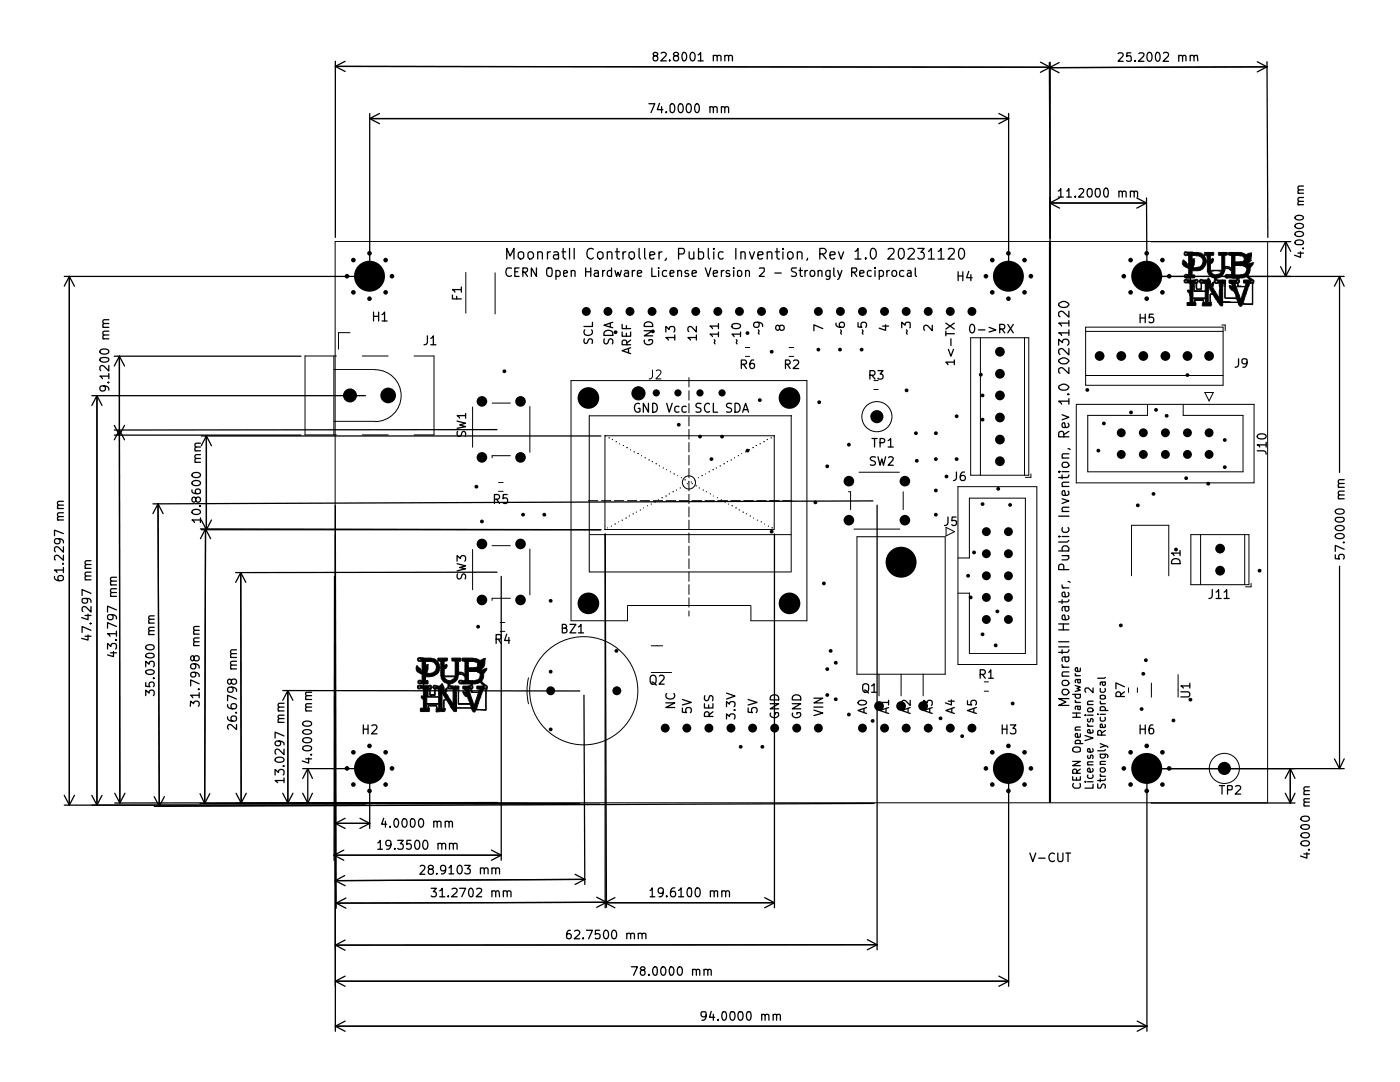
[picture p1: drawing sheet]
<svg xmlns="http://www.w3.org/2000/svg" width="279mm" height="216mm" viewBox="0 0 279 216" stroke-linecap="round" stroke-linejoin="round" font-family="sans-serif">
<g fill="none" stroke="#000" stroke-width=".2">
<path d="M66.9 48.2h186.1v112h-186.1zM93 54.4v8.1M98.8 54.4v8.3M236.1 51.9h.1M236.1 51.9l-.1 .3a.81 .81 0 0 0 .7 1.1M236.1 51.9a1.23 1.23 0 0 1 .9 1.4M236.2 52.2h.1M236.2 52.2l.3 .6 .6 .6M236.2 52.2l.5 .9M236.3 56.1h.1M236.3 50.6h.1M236.3 56.1h.2"/>
<path d="M236.3 55.1h.2M236.3 50.6h.2M236.5 56h.3l.1 .2-.3 .1zM236.5 50.5h.3l.1 .2-.3 .1zM236.6 50.4h.1M236.7 54.9h.1M236.7 53.3h.1M236.7 53.3l.5 .5v1.1l-.1-.1a.45 .45 0 0 0-.6 .1 .45 .45 0 0 0 0 .6h1v.4l-.9-.2-.3 .2 .1 .5 1 .1v1.5M236.7 54.9h.2v.4l-.4-.2M236.7 54.9l-.2 .2M236.9 56.1h1.6M237 58h.1"/>
<path d="M237 58l.1-.2 .3 .2M237 58l.4 .6M237.1 58h.1M237.1 53.4h.1M237.1 52.7h.1M237.1 52.7h.8M237.1 52.7v.7M237.1 58l.3 .3M237.1 51v1.7M237.4 58.6h.1M237.4 58.3h.1M237.4 58h.1"/>
<path d="M237.4 58.6l.1 1.8h-.6v.6h1.8l-.2-1.1h1.6l-.2 1.1h1.8l-.1-.6M237.5 59.9h.6M237.9 52.7h.1M237.9 51v.8l.4-.2M238.2 53.3h.1M238.2 53.3a1.39 1.39 0 0 0 1.8-1.6l-.7-.6h-2.7l-.3-.3 .2-.6 2.5 .2a1.83 1.83 0 0 1 1.8 1.7 1.83 1.83 0 0 1-1.6 1.9h-1.3v.9h.5v.6h-.8v.4l1.4-.1 .2 .3-.4 .5v1.1h.9v-1.1l-.3-.3 .1-.5 1.6 .1M238.2 56.5l-.1 2.9M238.2 52.2l-.3 .5M238.2 56.6v1.6h2.3v1.2h-3M238.2 52.2h.1M238.3 57.2h.1M238.3 51.6h.1"/>
<path d="M238.3 51.6l.1 .6-.2 1.1M238.4 56.5h.1M238.4 56.5l-.1 1.5M238.4 56.5l.3 .1 .1 1.1h1l.1-1.1h.6v1.5l-2.3-.1M238.6 56h.3v.3h-.3zM238.9 56.5h.1M239.4 56.1h.1M239.5 56.1l.1 .2M239.5 56.1l.2-.1h.2v.3h-.3M239.6 56.3h.1M240.3 58.1h.1M240.5 55.9h.1"/>
<path d="M240.5 57h1.4M240.8 51h.1M240.8 51h-.4v-.6h1.8v.5l-.5 .1-.1 .2v.7M240.8 51l.1 .1M240.9 51.1h.1M240.9 51.1l.1 3.2a2.66 2.66 0 0 0 1.4 1.2l-.1 .9 .2 .1M241 54.1h.1M241 52.2h.1M241 54.1h2.8M241 52.4h.7M241 52.2h.9M241.1 56h.1"/>
<path d="M241.1 55.8h.1M241.1 55.5h.1M241.1 55.5l.4 .4 .2 1 .1-.1M241.1 55.8v.2M241.1 55.5l-.2 .4M241.2 57.3h.1M241.2 57.3l-.1 3.1M241.2 57.4l.8 1.2M241.6 51.9h.1M241.6 54.1l.1 .1a.93 .93 0 0 0 .9 .7l.8-.3 .4-.5M241.7 52.4h.1M241.7 52.3h.1"/>
<path d="M241.7 52.3v.1M241.8 56.8h.1M241.8 52.3h.1M241.8 52.2h.1M241.8 51.7h.1M241.8 52.2v.1M241.8 52.3l-.1 .1M241.8 52.2l-.1 .1M241.9 52.2h.1M241.9 57h.1M242 51.6h.1M242 58.6h.1"/>
<path d="M242 56.7l-.1 .3M242 52l-.1 .2M242 51.6l-.4 .3M242 58.6l-.5 .1v1.7h-1.2M242.1 57.1h.1M242.1 51.8h.1M242.1 56.5h.1M242.1 51.8l-.1 .2M242.1 56.5l-.1 .2M242.2 56.3h.1M242.2 56.3h-.1l-.3 .5M242.2 56.3l-.2 1 1.3 2.2v-2.9l-.8-.1"/>
<path d="M242.3 56.2h.1M242.3 56.2h.2M242.4 55.6h.3M242.5 56.5h.1M242.6 56h.2l.2 .2-.3 .2-.2-.2zM242.7 55.6h.1M243.8 54.1h.1M243.8 55.9h.1M243.8 53.3h.7a1.08 1.08 0 0 1 1.3 .5h-.2a1.4 1.4 0 0 0-1.2-.5M244.2 56.6h.1M244.3 56.6h.1M244.3 56.6h-.2l-.1 .7v2.9"/>
<path d="M244.3 56.6l.1 2.9 2.4 .1 .3 .6M244.4 55.1h.1M244.4 53.3h.1M244.4 55.1l.5 .4h.8l1.2 .1-.2 .3h-1.4v.6l.2 .1M244.4 55.1h.3M244.6 54.9h.1M244.6 54.9l.3-.2 .9 .2M244.6 54.9l-.2 .2M244.7 55l.2-.1 .2 .3-.2 .1zM244.9 53.6h.1M244.9 53.3h.1M245.3 56.1h1.5"/>
<path d="M245.4 57h.1M245.4 57.1h.2M245.4 57v.1M245.5 56.6h.1M245.5 56.6h1.4M245.6 57.1h.1M245.6 57.1l.6 .8M245.6 57.1l.5 .7M245.7 51h.1M245.7 56.6l.3 .5-.6-.1M245.7 51l.1 .1M245.8 54.9h.1"/>
<path d="M245.8 52.3h.1M245.8 51.1h.1M245.8 54.9l-.1-.9-.5-.4h-.7a2.02 2.02 0 0 1-1.8 1.9v.2l.4 .2h1.5l-.1 3.5h2.2a1.88 1.88 0 0 0-1.1-1.7l-.2-.3v-.3M245.8 51.1v2.5a1.29 1.29 0 0 0-1.4-.4v-2.2l.5-.1v-.5h-1.7v.6l.6 .1v2.8h-2.2v-1.2a.66 .66 0 0 0 .5-.5 .66 .66 0 0 0-.1-.6M245.8 52.3h3M245.8 52.5h3M246.1 57.8h.1M246.5 51v1.3M246.5 52.9v2M246.5 56.6h.1M246.5 56.6l1.1 3.1M246.8 56h.3l.1 .1-.1 .2h-.3z"/>
<path d="M246.9 56.6h.1M246.9 56.6l.1 .6h1.5l-.9 2.5M247 56.8h.1M247.1 56.8v-.2a.45 .45 0 0 0 .1-.8v-.3h.2h.7l.6-.3 .8 .7h-1.3v.6l.5 .1-.2 .5h-1.4M247.1 56.8v.3M247.1 57.1h.1M247.1 52.9l1.1 .2M247.2 55.6h.1M247.2 56.1h.1M247.6 59.7h.1M248.2 56.1h1.4M248.2 53.1h.1"/>
<path d="M248.2 53.1l.5 .3a1.02 1.02 0 0 1-1 1.4l-1.9 .1M248.2 53.1h1.2M248.3 51.6h.1M248.3 51.6h.7M248.7 52.5h.1M248.7 52.5l.1 .1M248.8 52.6h.1M248.8 52.5h.1M248.8 52.3h.1M248.8 52.5v.1M249 51.6h.1M249.1 52.7h.1"/>
<path d="M249.4 53.1h.1M249.4 53h.1M249.4 50.8h.1M249.4 56.6h.1M249.4 56.6h.5v4h-1.5l-.3-.2M249.4 53v.1M249.4 50.8l-.4 .8M249.4 56.6l-1.3 3.8M249.5 53h.1M249.5 52.9h.1M249.6 52.9h.1M249.6 52h.1"/>
<path d="M249.6 52l-.7 .7h.9M249.7 52.9h.1M249.7 52.8h.1M249.7 52.8v.1M249.8 56h.1M249.8 52.8h.1M249.8 50.5h.1M249.8 50.5h-.6l-.5 .4-1.1-.5h-2.4v.5l.2 .1h1.7a1.19 1.19 0 0 1 1.2 .5v.3l-.3 .4-.8 .1M249.8 56l.3 .1-.1 .2-.4-.2M249.8 56l-.2 .1M249.8 52.8l-4 .1M249.8 50.5l-.2 1.5"/>
<path d="M249.8 52.7h.1M250.1 52.4h.1M250.1 56.5h.1M250.1 56.5l-.1 4.3-2-.1-.2 .3-.3 .1-.4-.7M250.1 52.4v.3a2.4 2.4 0 0 0-.8 1.8l-.2 .4 .7 .7a.49 .49 0 0 1 .4 .3 .49 .49 0 0 1-.1 .6M250.1 52.4l-.5 .1-.3 .2M66.6 71v15.8M66.6 73.7h8.2M67.1 71h-6.2v15.8h6.2M69.8 66.4h-2.2v3.3M72.3 71h5.2M74.9 73.8a5.2 5.2 0 0 1 5.2 5.1 5.2 5.2 0 0 1-5.2 5.2"/>
<path d="M82.6 71h4v15.8h-4M130.2 73.8v1.3a.57 .57 0 0 1-.7 .5M131 74l.6-.2 .2 .2 .1 .3-1 1.3h1M137.5 75.4v1.8M137.5 78v1.8M148.8 71.1h.8M148.8 69.3h.8M157.5 71.1h.9M157.5 69.3h.9M174.4 75.9h.9M174.4 77.7h.9M193.7 67.4h11.6v27.4h-11.6z"/>
<path d="M195.7 67.4v27.4M204.5 67.4v27.4M216.7 66.1h27.4M216.7 65.3h27.4v11.6h-27.4zM216.7 74.9h27.4M238.3 60.3h.1M238.3 60.1h.1M238.3 60.3l-.1 .1-.1-.2v-.6h2.4v.8M238.3 60.3v-.5h1.9l.1 .6M238.6 60.4h.1M240.1 60.2h.1M240.3 60.4h.1"/>
<path d="M240.5 60.4h.1M240.5 78.3h1.6l-.8 1.7zM241.6 60.4h.1M241.7 60.7h.1M243 60.2h.1M243 60.2l-.9-1.4h-.5v1.6M243 60.2l.7 .8h.3v-.6h3.1M243 60.2h4.1M243.8 64.9h.7v1.1M247.1 60.2h.1M247.1 60.4h1M248.1 60.4h.1"/>
<path d="M66.6 84.1h8.2M72.3 86.8h5.2M94.3 81.2v8M98.2 80.4h3.7M99.5 98h.9M99.5 96.3h.9M101.9 90.9h-3.7v.5M105.7 81.1v9.2M117.4 99.9h1.9M120.1 99.9h1.8M120.7 87h.1M120.7 87h33.8"/>
<path d="M120.7 87v18.7M121.5 87.4h.1M122.2 87.7h.1M122.6 99.9h1.9M122.9 88.1h.1M123.6 88.6h.1M124.4 88.9h.1M125.1 89.3h.1M125.2 99.9h1.9M125.8 89.7h.1M126.5 90.2h.1M127.3 90.5h.1"/>
<path d="M127.8 99.9h1.8M128 90.9h.1M128.7 91.4h.1M129.5 91.8h.1M130.1 92.1h.1M130.4 99.9h1.8M130.9 92.5h.1M131.4 99.7h.1M131.6 93h.1M132.1 99.3h.1M132.3 93.4h.1M132.8 99h.1"/>
<path d="M132.9 99.9h2M133 93.7h.1M133.5 98.5h.1M133.8 94.1h.1M134.3 98.1h.1M134.4 94.6h.1M135 97.8h.1M135.2 94.9h.1M135.5 99.9h1.9M135.7 97.4h.1M136 95.3h.1M136.4 96.9h.1"/>
<path d="M136.6 95.8h.1M137.2 96.5h.1M137.4 96.2h.1M137.5 80.5v1.9M137.5 83.1v1.9M137.5 85.7v1.9M137.5 88.3v1.9M137.5 90.8v2M137.5 93.5v1.8M137.5 96v2M137.5 98.6v1.9M137.9 96.2h.1"/>
<path d="M138.1 96.5h.1M138.1 99.9h1.9M138.6 95.8h.1M138.9 96.9h.1M139.4 95.3h.1M139.5 97.4h.1M140 94.9h.1M140.3 97.8h.1M140.7 99.9h1.9M140.8 94.6h.1M141 98.1h.1M141.5 94.1h.1"/>
<path d="M141.7 98.5h.1M142.2 93.7h.1M142.4 99h.1M142.9 93.4h.1M143.2 99.3h.1M143.3 99.9h1.9M143.7 93h.1M143.9 99.7h.1M144.4 92.5h.1M145.1 92.1h.1M145.9 91.8h.1M145.9 99.9h1.8"/>
<path d="M146.6 91.4h.1M147.3 90.9h.1M148 90.5h.1M148.4 99.9h2M148.8 90.2h.1M149.4 89.7h.1M150.2 89.3h.1M150.9 88.9h.1M151 99.9h1.9M151.6 88.6h.1M152.4 88.1h.1M153.1 87.7h.1"/>
<path d="M153.6 99.9h1.9M153.8 87.4h.1M154.5 87h.1M154.5 87v18.7M156.2 99.9h1.9M157.9 82.9v31.1M158 83h-40.4v31.1h40.3M169.3 98.1h.5v3.6M171.4 94.2h8.1M180.3 98.1v3.6M191.2 97.1h15.7v35.5h-15.7zM205.7 94.6v.6h-1.1"/>
<path d="M214.8 80.7h35.5v15.6h-35.5zM229 82.9h.1M229 80.7v2.2M236.1 80.7v2.2h12v11.2h-31v-11.2h11.9M94.3 109.6v8.1M98.2 108.9h3.7M101.9 119.4h-3.7v.4M105.7 109.6v9.1M117.8 106.7h40.1M120.6 105.7h33.8M121.2 105.3h.1M122 105h.1"/>
<path d="M122.7 104.6h.1M123.4 104.1h.1M124.1 103.8h.1M124.9 103.4h.1M125.6 103h.1M126.3 102.5h.1M127 102.2h.1M127.8 101.8h.1M128.4 101.3h.1M129.2 100.9h.1M130 100.6h.1M130.6 100.2h.1"/>
<path d="M137.5 101.2v1.9M137.5 103.8v1.9M137.5 106.3v2M137.5 109v1.8M137.5 111.5v2M137.5 114.1v1.9M137.5 116.7v1.9M137.5 119.3v1.9M144.6 100.2h.1M145.4 100.6h.1M146 100.9h.1M146.8 101.3h.1"/>
<path d="M147.5 101.8h.1M148.2 102.2h.1M148.9 102.5h.1M149.7 103h.1M150.4 103.4h.1M151.1 103.8h.1M151.9 104.1h.1M152.6 104.6h.1M153.3 105h.1M154 105.3h.1M170.4 105.6h9.2M171 107.1h17.6v27.4h-17.6z"/>
<path d="M188.8 105.2l1.7 .9-1.7 .8zM191.2 111.3h2.3v-11.9h11.1v31h-11.1v-12M191.2 118.4h2.3M193.5 118.4h.1M225.8 114.9v-10.1h7.5v10.1M237.7 106.7h11.6v10h-11.6zM239.6 106.7v10M248.4 106.7v10M249.7 116.4v.7h-1.1M83.1 132.8h.1M83.1 132.8v.2a1.22 1.22 0 0 0 1.1 1.5v1.3h-.7M83.1 132.8a1.4 1.4 0 0 1 1 1.5"/>
<path d="M83.2 133.3h.1M83.2 133.3l.7 .9M83.2 133.3l.3 .4M83.3 137.1h.1M83.3 137.1h.2M83.3 131.6h.2M83.4 133.5h.1M83.4 136.1h.2M83.5 135.8h.1M83.5 135.8v.6l1 .1v.3l-1-.1-.2 .2 .1 .5h.9l.2 .2-.1 1.3M83.5 137.1l.1-.2 .3 .2M83.5 131.6l.3-.2 .1 .3-.2 .1z"/>
<path d="M83.5 137.1l.2 .2 .2-.2M83.6 136l.3-.1 .1 .2-.3 .2zM83.6 133.8v.2l.5 .3M83.7 135.9h.1M83.7 131.2h.1M83.9 137.1h.1M83.9 137.1h1.7M84.1 134.3h.1M84.1 139l.2 .2M84.2 139h.1M84.2 139l.2 .4M84.2 133.6h.1"/>
<path d="M84.2 132v1.6M84.2 133.6v.8l-.2-.1M84.3 139.2h.1M84.3 139.2l.1 .2M84.4 139.5h.1M84.4 139.4h.1M84.4 138.9h.1M84.4 137.5h.1M84.4 139.5l.1 1.8h-.6v.7h1.8l-.1-.7M84.4 138.9h-.3v.4l.3 .2M84.9 133.6h.1M84.9 132v.8l.4-.2"/>
<path d="M85.2 137.5h.1M85.2 137.5l.1 1.6h2.2v1.3h-3M85.2 137.5v2.9M85.3 133.2h.1M85.3 138.9h.1M85.3 133.2l-.3 .4h-.8M85.3 133.2l-.4 .4M85.3 132.6h.1M85.3 132.6l.1 .9-.2 .8a1.29 1.29 0 0 0 1.6-.4 1.29 1.29 0 0 0-.1-1.7l-.7-.2-1.8-.1a.49 .49 0 0 1-.7 0 .49 .49 0 0 1-.1-.6h2.6a1.87 1.87 0 0 1 1.8 2 1.87 1.87 0 0 1-2 1.7h-.9v.8h.5v.7h-.8v.3l1.4-.1 .2 .5-.3 .3M85.4 137.5h.1M85.4 137.5v1.4M85.4 137.5h.3l.1 1.3h1.1v-1.2h.6v1.4l-2.1-.1"/>
<path d="M85.6 137l.2-.1 .1 .3-.2 .1zM85.9 137.5h.1M86.4 137.2l.3 .3v1.1h-.9l.1-1.1M86.4 137.2h.2M86.6 137.2h.1M87 137.2h.1M87 137.2l-.1-.3h-.2l-.1 .3M87 137.2l-.3 .1-.1-.1M87.3 139h.1M87.9 136.8h.1M87.9 132h.1M87.9 136.8l-.4 .1-.9-.2-.2 .5"/>
<path d="M87.9 136.8h.2M88 136.7h.1M88 136.7l-.1 .1M88 133.3h.7M88.1 135h2.7M88.1 135v.5a1.49 1.49 0 0 0 1.2 .9M88.1 136.5h.1M88.1 136.5l.4 .3 .2 1M88.1 136.7l.1 .2zM88.1 136.5l-.1 .2M88.2 136.7h.1M88.2 138.3h.1"/>
<path d="M88.2 138.3v3.1M88.2 138.3l.8 1.2M88.6 132.8h.1M88.6 132.8v-.7l.6-.2 .1-.6h-1.9v.5l.6 .3 .1 2.9M88.6 135a1.11 1.11 0 0 0 1.1 .8 1.11 1.11 0 0 0 1.1-.8M88.7 137.8h.1M88.7 133.3h.1M88.8 137.8h.1M88.8 133.3h.1M88.8 133.3h-.1M88.9 137.9l-1.4 .1M88.9 133.1l-.9 .1"/>
<path d="M89 139.5h.1M89 137.8l.2-.4-.3 .5M89 139.5l-.4 .1-.1 1.8h-1.1M89 137.8l-.1 .1M89.1 132.8h.1M89.1 132.8l-.2 .3M89.3 136.4h.1M89.3 137.2l.2 .3 .9 .1M89.3 137.2h.3M89.3 136.4v.8M89.4 136.6h.1M89.4 136.6h.3"/>
<path d="M89.6 137.1l.2-.1 .2 .2-.3 .1zM89.7 136.6a2.37 2.37 0 0 0 1.9 .3l-.1 3.5h2.3l-.4-1a.44 .44 0 0 0-.5-.5l-.5-.7M90.4 137.6h.1M90.4 137.6v2.9l-1.4-2.2 .2-.5v-.6l-.4 .4v.2M90.8 135h.1M90.8 136.9h.1M90.8 134.4h.7M91.1 137.6h.1M91.1 137.6v3.6M91.2 137.5h.1M91.2 137.5l.2 .1v2.9h2.4l.3 .7M91.2 137.5l-.1 .1"/>
<path d="M91.5 136.1h.1M91.5 134.4h.1M91.5 134.3h.8l.5 .4v.2a1.49 1.49 0 0 0-1.3-.5zM91.5 136.1h.2M91.6 135.8h.1M91.6 135.8l-.1 .3 .4 .4h1.9M91.9 134.5h.1M91.9 134.3h.1M91.9 135.9l.2 .1v.2h-.3l-.1-.1zM92.4 138.2h.1M92.4 138h.1M92.4 138.2h.3"/>
<path d="M92.4 138v.2M92.4 137.1h1.4M92.6 138.2h.1M92.6 138.2l.4 .3M92.7 138.2h.1M92.7 132h.1M92.7 137.5l.3 .7-.6-.2M92.7 138.2l.3 .3M92.7 132l2.1 .1a.61 .61 0 0 1 .5 .7 .61 .61 0 0 1-.7 .5l-1.1-.1v-1.2M92.8 135.8h.1M92.8 132h.1M92.8 132v2.5l-.4-.3-.9-.1v-2.1l.4-.1v-.6h-1.7l.1 .6 .5 .1v2.9h-2.2v-1.3l.3-.2a.58 .58 0 0 0 .3-.8l-.1-.1-.5 .3"/>
<path d="M92.8 135.8v-.7l-.3-.3-.4-.3h-.6a2.21 2.21 0 0 1-1.8 2.1M92.8 133.3h3.1M92.8 133.4h3M92.8 133.9h4M93 138.5l.2 .4M93 138.5l.2 .3M93.2 138.9h.1M93.2 138.8h.1M93.2 138.8v.1M93.6 137.5h.1M93.6 137.5l1.1 3.1M93.8 136.5h.1"/>
<path d="M93.8 136.5v.3l-1.4 .1v.6h1.5l.2 .7h1.4l-.8 2.4M93.8 137.1l.2-.2 .2 .2M93.8 137.1l.2 .2 .2-.2M94 137.8h.1M94.1 138h.1M94.2 136.6h.1M94.2 137.1h.1M94.2 136.6l.2 .7-.3 .2v.5M94.2 136.6l1.6-.5 .7 .8h-1.3v.6h.5l-.2 .6-1.4-.1M94.9 133.9l.3 .1M95.2 137.1h1.4M95.2 134a.93 .93 0 0 1 .6 1.1 .93 .93 0 0 1-1.1 .7h-3.1"/>
<path d="M95.2 134h1.3M95.3 132.6h.1M95.8 133.5h.1M95.8 133.4h.1M95.8 133.4v.1M95.8 133.3h.1M95.9 133.3h.1M96 132.6h.1M96 133.7h.1M96 133.7l.2 .1M96.1 132.4v.2h-.8M96.2 133.8h.1"/>
<path d="M96.2 133.8l1-.5-.7 1.1a2.09 2.09 0 0 1-.4 1.6l.7 .6 .3 .1 .2 .4M96.2 133.8h.7M96.3 132h.1M96.3 132l-.1 .2M96.4 134h.1M96.4 131.7h.1M96.4 137.6h.1M96.4 137.6l.5-.1v4.1l-1.8-.1M96.4 137.6l-1.3 3.9M96.4 131.7l-.4 .9M96.4 131.7l-.1 .3M96.5 134h.1"/>
<path d="M96.5 133.9h.1M96.5 133.9v.1M96.5 133.9l-.1 .1M96.6 133.9h.1M96.6 137.1l.3-.2 .2 .3-.2 .1zM96.6 133.9h-3.1v1.9M96.7 133.9h.1M96.8 133.9h.1M96.8 133.8h.1M96.8 131.4h.1M96.8 131.4l-1 .4-.8-.4-2.8-.1v.6l.5 .1M96.8 131.4l-.1 1.4-.7 .9"/>
<path d="M96.8 133.8v.1M96.9 133.8h.1M97.1 137.5h.1M97.3 137.1h.1M97.3 137.1l-.3 1.2v3.4l-2-.1-.3 .5M99.8 126h1M99.8 124.2h1M105.5 135.3l-.3 2.9 .3 2.2M125.2 120.8h24.7M125.2 121v2.9h-11.2v-48h47v48h-11.1v-2.9M130 134.2h4M130 128.9h2.2"/>
<path d="M137.5 121.9v1M175.4 134.5v4.4M179.8 134.5v4.4M184.2 134.5v4.4M196.4 136.1h.9M196.4 137.9h.9M225.2 137.2v1M227 137.2v1M229.8 136.3v2.8M235.1 134.6v4.5M84.5 140.9h.7M85.4 141.1h.1"/>
<path d="M85.4 141.1v-.3h1.8l.2 .6M85.4 141.1l-.1 .2h-.1v-.8h2.3v.9M85.6 141.3h.1M85.6 141.3l-.1-.4h1.6l-.1 1.2 1.7-.1 .1-.4M87.1 141.1h.1M87.4 141.4h.1M88.7 141.4h.1M88.8 141.6h.1M90.1 141.2l.5 .8h.5v-.7h3l.2 .6 .4 .2M93.9 141.2h.1M94.1 141.2h.1M94.1 141.2h-4.1l-.8-1.5h-.6v1.6l.2 .3"/>
<path d="M94.1 141.5h1M94.7 140.6h.1M94.7 142.1h.1M95.1 141.5h.1"/>
<circle cx="127.4" cy="78.5" r="1.31"/>
<circle cx="137.5" cy="96.3" r="1.31"/>
<circle cx="175" cy="83.1" r="3"/>
<circle cx="116.5" cy="137.8" r="10.8"/>
<circle cx="244.3" cy="153.3" r="3"/>
</g>
<g fill="none" stroke="#000" stroke-width=".25">
<path d="M66.9 12.2v35.2M66.9 13.2l2 1.1M68.9 12.2l-2 1M130.7 11.1l-.4-.4a.44 .44 0 0 1 .6-.3 .44 .44 0 0 1 .3 .6l-.7 .2-.2 .3 .1 .5 .3 .1h.4l.2-.3v-.3l-.4-.4M132 10.6l.2-.1h.4l.4 .2v.2l-.1 .2-1 1h1.1M133.6 12v.1M134.7 11.1a.34 .34 0 0 1-.3-.3 .34 .34 0 0 1 .3-.3h.4l.3 .3-.1 .2-.8 .3-.1 .5 .3 .3h.4l.3-.3-.1-.5-.2-.2M136.3 10.5h.1a.88 .88 0 0 1 .7 .8 .88 .88 0 0 1-.7 .8 1.35 1.35 0 0 1-.1-1.6zM137.9 10.6l.2-.1a.88 .88 0 0 1 .7 .8 .88 .88 0 0 1-.7 .8l-.2-.1-.2-.5zM139.3 11l.5-.5v1.6M139.3 12.1h1M142.4 11.1l.5-.1 .2 .2v.9"/>
<path d="M142.4 11v1.1M143.1 11.2l.3-.2 .5 .2v.9M144.7 11.2l.2-.2 .5 .2v.9M144.7 11v1.1M145.4 11.2l.3-.2 .4 .1 .1 1M207.6 12.4l2 1-142.7-.2M209.6 12.4v35.1l-.2-35M211.4 12.5l-3.8 1.9M223.1 10.7l.3-.2h.4l.4 .4-.1 .3-1 1h1.1M225.7 10.5h-.8l-.1 .8 .3-.2 .6 .1 .1 .9-.3 .1h-.4l-.3-.1M226.5 12.1v.1M227.3 10.7l.2-.2h.5l.2 .1 .1 .4-.1 .2-1 1h1.1"/>
<path d="M229.1 10.6l.2-.1a.96 .96 0 0 1 .4 1.6l-.2 .1a.96 .96 0 0 1-.4-1.6zM230.8 10.6l.1-.1a.96 .96 0 0 1 .4 1.6l-.2 .1a1 1 0 0 1-.3-1.6zM232.2 10.6l.3-.1h.4l.2 .1 .1 .4-.1 .2-1 1h1.1M235.2 11.2l.3-.2 .4 .1 .1 1.1M235.2 11v1.2M236 11.3a.35 .35 0 0 1 .3-.3 .35 .35 0 0 1 .4 .3v.8M237.5 11.2l.3-.2 .4 .1 .1 1M237.5 11v1.1M238.3 11.3l.2-.3 .5 .1 .1 1M250.9 12.3l2 1M252.9 12.3l.1 35.1M252.9 13.3l-43.5 .2 2 1"/>
<path d="M252.9 13.3l-2 1M73.8 22.6v31.7M73.8 23.7h127.5M73.8 23.7l1.9 1M75.7 22.6l-1.9 1.1M129.5 20.7h1.2l-.8 1.8M131.6 20.6l-.4 1.3h1.1M132 21.3v1.2M133 22.3v.2M133.9 20.8l.2-.1a.96 .96 0 0 1 .4 1.6l-.4 .2-.4-.4v-1.1zM135.6 20.8l.2-.1a.96 .96 0 0 1 .4 1.6l-.3 .2a.96 .96 0 0 1-.4-1.6zM137.2 20.8l.2-.1a.96 .96 0 0 1 .4 1.6l-.3 .2a.96 .96 0 0 1-.4-1.6z"/>
<path d="M138.8 20.9l.3-.2a1.01 1.01 0 0 1 0 1.8l-.3-.2-.2-.5zM141.7 21.5l.2-.2 .4 .1 .1 1.1M141.7 21.3v1.2M142.4 21.5l.2-.2 .4 .1 .1 1.1M144 21.5l.1-.1a.36 .36 0 0 1 .6 .1v1M144 21.3v1.2M144.7 21.5l.2-.2 .4 .1 .1 1.1M199.3 22.6l2 1.1M201.3 22.6v31.7M201.3 23.7l-2 1M209.5 39.5l.1 14.8M211.2 38.1l.5-.5v1.7"/>
<path d="M211.2 39.3h1M211.5 39.5l-2 1M212.9 38.1l.4-.5v1.7M212.9 39.3h.9M214.6 39.2v.1M215.3 37.8l.1-.1a.6 .6 0 0 1 .9 .2l-.1 .4-.9 1h1M217 37.9a.47 .47 0 0 1 .5-.3 .47 .47 0 0 1 .4 .3l.1 .7-.2 .6-.3 .1-.3-.1-.2-.2zM218.7 37.7l.6-.1a1.18 1.18 0 0 1-.1 1.7 .96 .96 0 0 1-.5-1.6zM220.4 37.7l.5-.2a1.29 1.29 0 0 1 0 1.8 .96 .96 0 0 1-.5-1.6zM223.3 38.3l.1-.1a.36 .36 0 0 1 .6 .2v.9M223.3 38.1v1.2M224 38.4l.2-.3 .5 .1v1.1"/>
<path d="M225.6 38.3l.2-.2 .5 .1 .1 1.1M225.6 38.1v1.2M226.4 38.4l.1-.3 .4 .1 .1 1.1M226.9 39.5l1.9 1M228.8 39.5l.1 14.8M259 38.6h1.1M260.1 39.4l-1 .1-.1 .4 .3 .3M260.1 37.9h-.8a.37 .37 0 0 0-.3 .3 .37 .37 0 0 0 .2 .4M260.1 37.1l-1 .1-.1 .4 .3 .3M12.8 55.2h60.1M13.8 55.2v105.5M13.8 55.2l1.1 1.9"/>
<path d="M13.8 55.2l-1 1.9M90.3 58.9v.7h1.8M91.1 59.1v.5M92.1 57.8h-1.8l.5 .5M92.1 57.3v1M101.1 51.7v-2.1l.7 1.5 .8-1.5v2.1M102.1 53.5h-.8a.88 .88 0 0 0-.4 1.1 .88 .88 0 0 0 1.1 .5l.1-.1M102.7 54.2h.6M103.5 50.4a.69 .69 0 0 1 .9 0l.1 .9-.2 .2a.54 .54 0 0 1-.5 .2 .54 .54 0 0 1-.4-.4zM103.6 53.5h-.9v1.7h.9M104.3 54.3h.6l.3-.2 .1-.4-.2-.2h-.8v1.7M104.7 54.3l.6 .9"/>
<path d="M105.5 50.4l.2-.2a.63 .63 0 0 1 .8 .5v.6l-.5 .4h-.3l-.3-.4zM107.1 53.5v1.7l-1.1-1.7v1.7M107.3 50.4l.1-.1a.54 .54 0 0 1 .8 .3v1.1M107.3 50.2v1.5M109.2 53.6l.1-.1h.7a1.37 1.37 0 0 1-.1 1.7 .6 .6 0 0 1-.8-.6zM109.3 50.2v1.5M109.9 50.2a.46 .46 0 0 0-.6 .5M110.5 50.3h.8l.2 .3v1.1M111 54.1l.5-.1 .3 .3v.5l-.2 .3h-.6M111 54v1.8M111.5 50.8h-.8a.47 .47 0 0 0-.3 .5 .47 .47 0 0 0 .3 .4h.5l.3-.2M112.1 50.2h.8"/>
<path d="M112.4 49.6v1.7l.5 .4M112.5 54.6l.7-.2v-.3l-.6-.1-.1 .2 .1 .9h.6M113.7 49.6v2.1M114 54.1l.3-.1 .4 .1 .1 1.1M114 54v1.2M114.6 49.6v2.1M116.9 54.2h1M116.9 53.5v1.7M117.9 53.5v1.7M118.4 49.7a.84 .84 0 0 0-1 .1 .84 .84 0 0 0-.3 1l.2 .5 .5 .4h.3l.3-.3M118.7 54.1h.6l.1 1.1M119.3 50.4a.61 .61 0 0 1 1.1 .3l-.1 .7a.55 .55 0 0 1-.6 .3 .55 .55 0 0 1-.4-.4z"/>
<path d="M119.4 54.4l-.6 .1a.35 .35 0 0 0-.2 .3 .35 .35 0 0 0 .2 .4l.6-.1M120.3 54v1.2M120.7 54l-.4 .3M121.2 50.4l.3-.2 .5 .1 .1 1.4M121.2 50.2v1.5M122 54.1l-.5-.1-.3 .3v.5l.2 .3h.6M122 53.5v1.7M122.7 54l.4 1.2 .2-.9 .4 .9 .3-1.2M122.8 50.2h.9M123.1 49.6v1.7l.3 .4h.3M124.3 50.2v1.5M124.7 54.1h.6l.1 1.1"/>
<path d="M124.9 50.2a.46 .46 0 0 0-.6 .5M125.4 54.4l-.6 .1a.35 .35 0 0 0-.2 .3 .35 .35 0 0 0 .2 .4l.6-.1M125.6 50.4l.3-.2 .5 .1a1.02 1.02 0 0 1 .1 1.1l-.2 .3h-.4l-.3-.3zM126.2 54v1.2M126.7 54l-.3 .1-.2 .2M127.2 54.6l.9-.2-.1-.3-.5-.1-.3 .2 .1 .9h.7M127.5 49.6v1.7l.3 .4M128.6 49.6v1.7l.3 .4M129.7 50.9l1-.1-.2-.5-.6-.1-.2 .4v.9l.2 .2h.4l.2-.2M130.1 53.5v1.7h.8M131.4 53.5h.1M131.4 54v1.2"/>
<path d="M131.5 50.2v1.5M132.1 50.2l-.5 .2-.1 .3M133 51.5l-.1 .4h-.2M133.1 54.1l-.6-.1-.3 .3v.5l.2 .3h.7M133.7 54.6l.8-.2-.1-.3-.5-.1-.2 .2 .1 .9h.6M135.3 54.1l.2-.1 .4 .1 .1 1.1M135.3 54v1.2M135.4 50.7h.9a.63 .63 0 0 0 .1-1l-1-.1v2.1M137.4 54.1l-.5-.1-.2 .2 .1 .3 .6 .2v.4h-.7M137.5 50.2l.1 1.3 .5 .2 .4-.3M138.1 54.6l.9-.2-.1-.3-.5-.1-.3 .2 .1 .9h.7M138.5 50.2v1.5"/>
<path d="M139.4 50.3h.8a1.02 1.02 0 0 1 .1 1.1l-.2 .3h-.4l-.3-.2M139.4 49.6v2.1M140.8 53.5l.5 1.7 .6-1.7M141.3 49.6v1.7l.3 .4M142.4 54.6l.8-.2-.1-.3-.5-.1-.2 .2v.9h.7M142.4 49.6v.1M142.4 50.2v1.5M144 54v1.2M144.3 50.3h-.7a1.02 1.02 0 0 0-.1 1.1l.2 .3h.4l.2-.2M144.5 54l-.4 .1-.1 .2M145.6 54.1l-.4-.1-.3 .2 .1 .3 .6 .2v.4h-.7M146.4 53.5h.1"/>
<path d="M146.4 54v1.2M146.9 49.6v2.1M147.2 54.1l.2-.1 .6 .1v.7l-.1 .3-.5 .1-.2-.2zM147.9 50.4l.2-.2 .5 .1 .1 1.4M147.9 50.2v1.5M148.8 54.1l.3-.1 .4 .1 .1 1.1M148.8 54v1.2M149.6 50.2l.5 1.5 .5-1.5M151.3 50.9l1-.1-.1-.5-.7-.1-.2 .4v.9l.2 .2h.4l.3-.2M151.6 53.5h.8l.1 .6-1 1.1h1M153.1 50.4l.4-.2 .5 .1v1.4M153.1 50.2v1.5"/>
<path d="M154.6 54.5h1.3M154.7 50.2h.9M155.1 49.6v1.7l.2 .4h.3M156.3 49.6v.1M156.3 50.2v1.5M157.4 50.3l.1-.1a.63 .63 0 0 1 .8 .5v.6l-.4 .4h-.4l-.2-.3a1.02 1.02 0 0 1 .1-1.1zM159 53.5h-1v.6l.8 .3 .2 .4-.4 .4-.7-.1M159.1 50.4l.1-.1a.54 .54 0 0 1 .9 .3v1.1M159.1 50.2v1.5M159.5 54h.6M159.7 53.5v1.4l.1 .2 .3 .1M160.7 54v1.2"/>
<path d="M161.2 54l-.4 .1-.1 .2M161.2 51.5l-.2 .4M161.8 54.1l.2-.1 .5 .1 .1 .7-.2 .3-.4 .1-.2-.2zM163.3 54.1l.2-.1 .5 .1v1.1M163.3 54v1.2M163.6 50.7l1-.1a.55 .55 0 0 0 .3-.6 .55 .55 0 0 0-.4-.4h-.9v2.1M164.1 50.7l.8 1M165.6 54v1.4l-.3 .4-.4-.1M165.6 54.1l-.5-.1-.3 .3v.5l.2 .3h.6M165.6 50.9l1.1-.1v-.2a.6 .6 0 0 0-1-.3v1.2l.3 .2 .6-.2M166.4 53.5v1.4l.3 .3M167.2 54l.4 1.2"/>
<path d="M167.3 50.2l.5 1.5 .6-1.5M168 54l-.6 1.6-.2 .2M170 54.3l.8-.1 .2-.2-.1-.5h-.9v1.7M170.4 54.3l.6 .9M170.6 50.2l.3-.1 .3-.5v2.1M170.6 51.7h1.2M171.6 54.6l.8-.2-.1-.3-.5-.1-.2 .2 .1 .9h.6M172.8 51.4v.3M173.9 54.1l-.5-.1-.3 .3v.5l.2 .3h.6M173.9 49.7l.2-.1a.68 .68 0 0 1 .8 .7 .98 .98 0 0 1-.8 1.4 1.7 1.7 0 0 1-.2-2zM174.6 53.5h.1M174.6 54v1.2"/>
<path d="M175.5 54.1l.5-.1 .3 .3v.5l-.2 .3h-.6M175.5 54v1.8M177 54v1.2M177.2 49.7a.87 .87 0 0 1 1.1 0v.7l-1.1 1.3h1.2M177.5 54l-.3 .1-.2 .2M178.1 54.1l.2-.1 .6 .1v.7l-.1 .3-.5 .1-.2-.2zM179.4 49.7l.6-.1a1.23 1.23 0 0 1 .4 1.7l-.6 .4a1.33 1.33 0 0 1-.4-2zM180.4 54.1l-.5-.1-.4 .3v.5l.2 .3h.7M181.1 54.1h.6l.1 1.1M181.2 49.7l.9-.1 .2 .1 .2 .5-1.4 1.5h1.4M181.8 54.4l-.5 .1a.35 .35 0 0 0-.3 .3 .35 .35 0 0 0 .3 .4l.5-.1M182.7 53.5v1.4l.2 .3"/>
<path d="M183.2 49.6h1.2l-.6 .7 .5 .1 .1 .4v.6l-.4 .3h-.6l-.2-.3M185.3 50.2l.6-.6v2.1M185.3 51.7h1.2M187.2 50.2l.3-.1 .3-.5v2.1M187.2 51.7h1.2M189.3 49.7h.1a.92 .92 0 0 1 1 0v.7l-1.2 1.3h1.3M191.2 54.2v1.8M191.2 55.1h.9M191.5 49.7l.2-.1a.68 .68 0 0 1 .8 .7 .98 .98 0 0 1-.8 1.4 1.7 1.7 0 0 1-.2-2zM192.1 54.2v1.8M193.3 54.1l-.4 1.3h1.1M193.8 54.8v1.2"/>
<path d="M209.5 40.5h19.3M209.5 40.5l2 1M228.8 40.5l-1.9 1M229.7 55.2h38.6M229.7 48.2h27.9M255.6 53.2l1 2M256.6 48.2v7M256.6 48.2l1 2M256.6 48.2l-1 2M257.6 53.2l-1 2M258.5 48.1a1.1 1.1 0 0 1 1.6 .2v.3l-.3 .2h-1l-.4-.3zM258.5 46.4a1.1 1.1 0 0 1 1.6 .2 .89 .89 0 0 1-.8 .6 .89 .89 0 0 1-.9-.6z"/>
<path d="M258.5 44.8a1.1 1.1 0 0 1 1.6 .2 .89 .89 0 0 1-.8 .6 .89 .89 0 0 1-.9-.6zM258.5 43.2a1.03 1.03 0 0 1 1.6 .3 .98 .98 0 0 1-1.7-.1zM259 50.5h1.1M259 40.8h1.1M259.5 50.2v1.1l-1.1-.4M260 49.6h.1M260.1 40.2l-1 .1-.1 .4 .2 .1M267.3 55.2v39.1M267.3 55.2l1 1.9M267.3 55.2l-1 1.9M18.3 78.9h54.6M19.3 78.9v81.8"/>
<path d="M19.3 78.9l1.1 2M19.3 78.9l-1 2M20 71.5l1-.2 .5 .1 .2 .3a.96 .96 0 0 1-1.6 .4l-.2-.3zM20 69.9a1.18 1.18 0 0 1 1.7 .2 .96 .96 0 0 1-1.6 .4l-.2-.3zM20.5 67.6h1.2M20.5 65.3h1.2M20.7 77l.3 .3v.4l-.3 .3h-.4l-.3-.2-.1-.5 .2-.2a1.18 1.18 0 0 1 1.6 .4v.3M21.5 76.3h.2M21.7 75.1h-1.8l.5 .5M21.7 72.9v1.1l-1-1-.3-.1-.3 .1-.2 .3v.4l.2 .3M21.7 66.8l-1.1 .1-.1 .5 .2 .2M21.7 66.1l-1.1 .1-.1 .4 .3 .2"/>
<path d="M21.7 64.6h-1.1l-.1 .5 .2 .2M21.7 63.8l-1.1 .1-.1 .4 .3 .3M21.7 74.5v1.1M22.8 71.1h37.3M23.8 71.1v15.7M23.8 71.1l1 1.9M23.8 71.1l-1 1.9M74.5 62.3v1.7M74.5 63.1h1.1M75.6 62.3v1.7M76.2 62.8l.5-.5v1.7M76.2 64h1.1"/>
<path d="M85.3 67v1.3a.57 .57 0 0 1-.7 .5M86 67.5l.5-.5v1.8M86 68.8h1M116.6 67.6a.67 .67 0 0 0 .2 .9l.4-.1 .2-.5a.47 .47 0 0 1 .4-.3 .47 .47 0 0 1 .4 .3v.6M116.7 65.8a.75 .75 0 0 0 .1 1 .75 .75 0 0 0 1 0 .62 .62 0 0 0 .3-1M118.2 64.3v.8h-1.7M120.6 67.6l-.1 .7 .2 .2h.5l.3-.7 .5-.2 .3 .3-.1 .7M120.6 66.2a.95 .95 0 0 1 1.1-.2 .95 .95 0 0 1 .6 .9h-1.8zM121.8 64.5v.7M122.3 64.3l-1.8 .6 1.8 .5M124.2 66.2v.9h1.7v-.9M124.2 64.7v.9h1.7"/>
<path d="M125 65v.6M125 66.5v.6M125.1 68.8l-.1-.8-.2-.1h-.5l-.1 .3v.6h1.7M125.4 69.6v.8M125.9 69.4l-1.7 .6 1.7 .6M125.9 67.9l-.8 .6M128.6 66h1.7l-1.7 1h1.7M128.6 67.9a.78 .78 0 0 0 .8 .9 .78 .78 0 0 0 .8-.9l-.7-.1v.2M128.6 64.6a.9 .9 0 0 1 1.1-.3 .9 .9 0 0 1 .6 .8h-1.7zM132.9 66.2v-1.1l.7 .6 .1-.5h.8l.2 .3v.5l-.2 .2M134.7 67.4h-1.8l.5 .5M134.7 66.8v1.1"/>
<path d="M139 67.4h-1.7l.5 .5M139 65.1v1.1l-1-1-.2-.1-.3 .1-.2 .3v.4l.2 .3M139 66.8v1.1M142.5 67.8l.2 .2-.2 .4 .2 .2M143.4 66.7h-1.7l.5 .5M143.4 65.1h-1.7l.5 .5M143.4 64.6v1M143.4 66.2v1M146.1 64.8a1.18 1.18 0 0 1 1.7 .2 .95 .95 0 0 1-.8 .6 .95 .95 0 0 1-.9-.5zM146.9 67.8l.2 .2-.2 .4 .2 .2M147.8 66.7h-1.7l.4 .5M147.8 66.2v1"/>
<path d="M148 72.7l.9-.1v-.6l-.3-.2h-.6v1.7M148.4 72.7l.6 .8M150.4 71.8h-.3l-.2 .2a1.23 1.23 0 0 0 0 1.5l.6-.1 .1-.6-.4-.3h-.3l-.3 .3M151.2 64.3l.3 .3-.1 .5-.2 .2h-.5l-.2-.2-.1-.5 .2-.2a1.18 1.18 0 0 1 1.6 .4v.3M151.3 65.8l.2 .3-.2 .3 .2 .3M155.6 65.2l.2-.3h.4l.3 .3-.2 .6-.5 .1-.4-.9-.3-.1-.2 .2-.1 .5 .2 .2 .2 .1 .4-.3M156.8 72.7l.8-.1v-.6l-.2-.2h-.6v1.7M157.1 72.7l.6 .8M158.4 72l.2-.2h.4l.3 .2 .1 .3-.1 .3-1 .9h1.1M164.2 65.6l-1.8-.8v1.2M166.8 64.5a.7 .7 0 0 0 .8 .8h.7a.6 .6 0 0 0 0-1h-.5l-.3 .3v.4l.3 .3M167.8 65.8l.1 .3-.1 .3 .1 .3"/>
<path d="M171.2 64.4v.8l.8 .1-.2-.2 .1-.6 .3-.2 .6 .1 .1 .2v.5l-.1 .2M172.1 65.8l.2 .3-.2 .3 .2 .3M173.6 74.9l.9-.1 .1-.3-.1-.4-.2-.1h-.7v1.6M174 74.9l.6 .7M175.2 74h1l-.6 .6 .5 .2v.7l-.2 .1h-.5l-.2-.1M176.1 65.1h1.2M176.7 64.8v1.1l-1.2-.4M180 65.4v-1.1l.6 .6 .2-.5h.8v1M180.9 65.8l.2 .3-.2 .3 .2 .3M186.1 64.9v1.1l-1-1-.2-.1-.4 .1-.1 .2v.5l.1 .2M188.8 66.1v.9M188.8 66.6h1.7"/>
<path d="M188.8 64.5l1.7 1.2M189.3 69.7l.5 1.4 .5-1.4M189.8 67.6v1.4M190.5 72.3h-1.7l.4 .5M190.5 71.8v1M190.5 64.5l-1.7 1.2M193.8 64.8l.1-.1a.89 .89 0 0 1 .6 .9 .89 .89 0 0 1-.6 .8 1.06 1.06 0 0 1-.1-1.6zM195.3 65.8h1.3M197.4 65.3l1.4 .5-1.4 .4M199.5 65.7l.9-.1 .1-.3-.1-.4-.2-.2h-.7v1.7M199.9 65.7l.6 .7M201.1 64.7l1.1 1.7"/>
<path d="M202.2 64.7l-1.1 1.7M211.3 68.9v-1.2l.7 .7a.49 .49 0 0 1 .5-.7h.4l.4 .4v.5l-.2 .3M211.4 77l.6-.3a1.02 1.02 0 0 1 1.3 .6 1.14 1.14 0 0 1-1.1 .6 1.14 1.14 0 0 1-.9-.7zM211.4 71.8l.6-.4a1.02 1.02 0 0 1 1.3 .7 1.09 1.09 0 0 1-1.1 .6 1.09 1.09 0 0 1-.9-.8zM211.4 60.5l.6-.3a1.02 1.02 0 0 1 1.3 .6 1.14 1.14 0 0 1-1.1 .6 1.14 1.14 0 0 1-.9-.7zM213.1 78.7h.2M213.3 73.4v1.1l-1.4-1.1-.5 .1-.1 .2v.5l.2 .3M213.3 69.6v1.2l-1.2-1.2h-.4l-.3 .1a.74 .74 0 0 0 .1 1M213.3 66.4h-2l.6 .5M213.3 64.5h-2l.6 .6M213.3 62.1v1.2l-1.4-1.2-.5 .2-.1 .1v.5l.2 .3M213.3 64v1.1"/>
<path d="M213.3 65.8v1.1M213.3 79.5v1.1M227.5 62.7v1.7M227.5 63.5h1.1M228.6 62.7v1.7M230.2 62.7h-.8l-.1 .8 .2-.2 .6 .1 .1 .2v.6l-.3 .2h-.4l-.2-.2M247.2 71.6v1.2a.57 .57 0 0 1-.7 .5M248.9 72.3l-.4 .3h-.3l-.3-.3v-.6h.9a1.18 1.18 0 0 1-.4 1.6h-.4M22.8 86.8h37.3M22.8 84.9l1 1.9M23.8 85.8l.1 74.4M23.8 85.8l1 2"/>
<path d="M23.8 85.8l-1 2M24.8 84.9l-1 1.9M38.3 97.7v.4a1.22 1.22 0 0 0 1.7 .2l-.1-.6-.6-.1-.3 .3 .1 .5 .2 .1M38.4 96.1a.96 .96 0 0 1 1.6 .4 .95 .95 0 0 1-.9 .4 .95 .95 0 0 1-.8-.6zM38.4 94.5a.96 .96 0 0 1 1.6 .4 .95 .95 0 0 1-.9 .4 .95 .95 0 0 1-.8-.6zM38.9 92.2h1.1M38.9 90h1.1M39.1 99.5l.3-.3 .4 .1 .2 .2-.1 .5-.5 .2-.2-.2-.3-.7-.3-.1-.2 .2-.1 .5 .2 .2 .2 .1 .4-.3M40 91.5l-1 .1-.1 .4 .2 .2M40 90.7l-1 .1-.1 .4 .3 .3M40 89.2l-1 .1-.1 .4 .2 .3M40 88.4l-1 .1-.1 .4 .3 .3"/>
<path d="M40.2 87h79.7M41.2 87v18.7M41.2 87l1 1.9M41.2 87l-1 1.9M91.2 84l1.7 .5-1.2 .3 1.2 .3-1.7 .4M91.3 86.1l-.1 .6 .2 .3h.5l.3-.8 .4-.1 .3 .3-.1 .7M92.9 82.9h-1.7l.5 .5M92.9 82.5v.9M98.7 99.6l.8-.1 .2-.2-.1-.5-.2-.1h-.7v1.8M99.1 99.6l.6 .9M99.2 85.7l-76.4 .1M101.2 98.7h-.7l-.1 .8 .2-.1h.4l.3 .3-.1 .6-.2 .2h-.4l-.2-.2"/>
<path d="M127.6 80.6a.87 .87 0 0 0-1 .6 .87 .87 0 0 0 .6 1.1l.5-.2v-.6h-.3M129.4 80.5v1.8l-1-1.8v1.8M130.3 80.5a.89 .89 0 0 1 .9 .9 .89 .89 0 0 1-.9 .9zM133.1 80.5l.5 1.8 .6-1.8M135.5 81.2l-.5-.1-.3 .3v.5l.1 .3h.7M136.9 81.2l-.5-.1-.3 .3v.5l.2 .3h.6M139.9 80.6l-.7-.1-.2 .1v.6l.7 .3 .2 .4-.3 .4-.7-.1M141.6 80.6a.68 .68 0 0 0-.8 .1 .68 .68 0 0 0-.2 .8 .62 .62 0 0 0 .3 .6 .62 .62 0 0 0 .7 0M142.4 80.5v1.8h.8M146 80.6l-.7-.1-.2 .1v.6l.7 .3 .2 .4-.3 .4-.7-.1M146.7 80.5a.9 .9 0 0 1 1 .9 .9 .9 0 0 1-1 .9zM148.2 82.3l.6-1.8 .6 1.8"/>
<path d="M148.4 81.7h.8M174 87.5h1M174.2 99.9l-143.7 .6M174.5 87.5v1.7M174.7 91.2a.74 .74 0 0 0-1 .2l.2 .4 .6 .3 .2 .2-.1 .4-.2 .1h-.7M175.2 91.1l.4 1.7 .4-1.2 .3 1.2 .4-1.7M175.6 88.3h.8l.2-.5-.4-.3h-.6v1.7M177.2 87.9l.6-.4v1.7M177.2 89.2h1.1M177.3 91.3l.1-.1a.6 .6 0 0 1 .9 .2l-.1 .4-1 1h1.1M190.9 94.2v1.2a.55 .55 0 0 1-.6 .5M192.5 94.2a.7 .7 0 0 0-.9 .8v.5l.2 .3 .5 .1 .4-.4v-.3l-.4-.3-.5 .1-.2 .2"/>
<path d="M211.3 94.1l.1 .2 .1-.2-.1-.1-.1 .1h.2M212 99.5l1.3 .4-1.3 .6M212 82.8l1.3 .5-1.3 .5M212 94.8v.7M212 97.1h1.3M212 94.1h1.3M212 91.4h1.3M212.1 92.3l.8-.1 .4 .5v.2l-.4 .4h-.6l-.3-.4zM212.3 87.2v-.7a.46 .46 0 0 0-.6-.4l-.3 .1-.1 1h2M213.1 98l.2 .2v.4l-.3 .2h-1v-.8l.5-.1 .1 .9M213.1 89.5l.5 .2M213.1 84.5l.2 .2v.3l-.2 .2h-1.1a.6 .6 0 0 1 .2-.8h.3l.1 .9"/>
<path d="M213.3 96.2h-1.1a.49 .49 0 0 0-.1 .9M213.3 94.8l-.3 .5h-1.7M213.3 90.5h-1.1a.52 .52 0 0 0-.1 .9M213.3 80.1h-2l.6 .5M213.3 86.1l-1 .6M250.9 90h1.3a.57 .57 0 0 1 .5 .6M251 86.8a1.18 1.18 0 0 1 1.7 .2 .96 .96 0 0 1-1.6 .4l-.2-.2zM252.7 88.8h-1.8l.5 .4M252.7 88.3v.9M267.1 99.5h1.2M267.1 97.2h1.2M268.3 98.8h-1.1l-.1 .5 .1 .2"/>
<path d="M268.3 98l-1.1 .1-.1 .4 .2 .3M268.3 96.5l-1.1 .1-.1 .4 .1 .2M268.3 95.7l-1.1 .1-.1 .4 .2 .3M10.9 115a.7 .7 0 0 0 .7 .9h.7l.3-.2 .1-.5-.2-.3-.6-.1-.3 .2v.5l.3 .4M11.5 103.8h1.2M11.5 101.5h1.2M11.6 107.5l.4 .3v.4l-.4 .3h-.4l-.2-.2-.1-.5 .1-.2a1.18 1.18 0 0 1 1.7 .4v.3M12.5 112.5h.2M12.7 113.7h-1.8l.5 .6M12.7 110.8v1l-1.3-1-.4 .1-.1 .2v.4l.1 .2M12.7 109.1v1.1l-1.1-1-.2-.1-.4 .1-.1 .2v.5l.1 .2M12.7 106.5l-1.8-.7v1.1"/>
<path d="M12.7 103.1l-1.1 .1-.1 .4 .1 .2M12.7 102.3l-1.1 .1-.1 .4 .2 .3M12.7 100.8h-1a.37 .37 0 0 0-.2 .3 .37 .37 0 0 0 .1 .4M12.7 100l-1.1 .1-.1 .4 .2 .3M12.7 113.2v1.1M17 115.7h1.2M17 113.4h1.2M17.1 119.4h.2l.2 .3-.1 .5-.3 .2-.5-.1-.2-.3 .2-.6h1.1a.63 .63 0 0 1 .5 .8M18.2 118.4l-1.8-.8v1.2M18.2 114.9l-1.1 .1-.1 .4 .1 .3M18.2 114.2l-1.1 .1-.1 .4 .2 .2M18.2 112.6l-1.1 .1-.1 .5 .1 .2"/>
<path d="M18.2 111.9l-1.1 .1-.1 .4 .2 .2M22.1 119h1.1M22.1 116.7h1.1M23.2 118.2l-1.1 .1v.4l.1 .3M23.2 117.5l-1.1 .1v.4l.2 .2M23.2 115.9l-1.1 .1v.5l.1 .2M23.2 115.2l-1.1 .1v.4l.2 .2M31.5 100.5l.3 60.4M31.5 100.5l1.1 2M31.5 100.5l-1 2M38.4 101.9a.96 .96 0 0 1 1.6 .3 .95 .95 0 0 1-.9 .5 .95 .95 0 0 1-.8-.6zM39.8 101h.2"/>
<path d="M40 103.8h-1.7l.5 .5M40 105.5l79.9 .2h-79.7M40 103.3v1M40.2 103.8l1 1.9M41 105.5l-.2 54.8M41 105.5l1 2M41 105.5l-1 2M42.2 103.8l-1 1.9M48 114.3l.1 45.9M48 114.3l1.1 1.9M48 114.3l-1 1.9M66.8 115l-.1 56.7"/>
<path d="M66.9 106.7l.2 74.5M66.9 100.9v104.9M91.2 112.5l1.7 .4-1.2 .3 1.2 .3-1.7 .4M91.2 112v-1.1l.7 .6 .2-.5h.7l.1 .2v.5l-.1 .3M91.3 114.5l-.1 .7 .4 .3 .4-.1 .3-.8h.5l.1 .2-.1 .7M99.2 114.2l-52.2 .1M100 115v56.7M154.6 106.6v74.5M175 100.8v88.7M189.2 103.2v1.1a.57 .57 0 0 1-.7 .6M190.8 103.2h-.8l-.1 .7h.9v.8l-.3 .2-.6-.2M211.3 107.1h.2"/>
<path d="M211.3 109.9h2M211.3 103h2M212 116.7v.4l.3 .2M212 119.7v.7M212 117.3h1.3M212 110.9h1.3M212 107.1h1.3M212 102.1h1.3M212 109.9a.72 .72 0 0 1 .3-1h.6l.4 .4-.2 .6M212 105.3v.6l.3 .3h.6l.4-.3v-.4l-.2-.2M212.3 113.7l-.1-1-.2-.1-.6 .1-.1 1h2M213.1 110.9l.2 .2v.3l-.3 .3h-1"/>
<path d="M213.1 118.2l.2 .2v.4l-.3 .3-1-.1v-.8h.5l.1 .9M213.1 116l.5 .2M213.3 119.7v.1l-.3 .3h-1.7M213.3 107.8l-.3 .4h-1.7M213.3 101.2l-1.3 .1v.4l.1 .4M233.9 111.8a.9 .9 0 0 1 1.1-.3 .9 .9 0 0 1 .5 1h-1.7zM235.5 110.4h-1.7l.5 .5M235.5 109.9v1M241.9 117.6v1.3a.57 .57 0 0 1-.6 .5M242.7 118.2l.5-.6v1.8M242.7 119.4h1M244.3 118.2l.5-.6v1.8"/>
<path d="M244.3 119.4h1M266.5 110.7v.8h.8l-.1-.2v-.5l.3-.2 .6 .1 .2 .3-.2 .5M266.6 106.7a1.18 1.18 0 0 1 1.7 .2 .96 .96 0 0 1-1.6 .4l-.2-.2zM266.6 105.1a1.18 1.18 0 0 1 1.7 .2 .96 .96 0 0 1-1.6 .4l-.2-.2zM266.6 103.4l.2-.2h1.1l.4 .4a.96 .96 0 0 1-1.6 .4l-.2-.2zM266.7 101.7a.96 .96 0 0 1 1.6 .4 1.11 1.11 0 0 1-1.8 0zM267.3 113v40.4M268.1 108.2h.2M268.3 109.6l-1.8-.8v1.2M17 127h1.2M17 122.8h1.2M17.6 126.7v1l-1.3-.3"/>
<path d="M17.6 122.6v1.1l-1.3-.5M18 124.4h.2M18.2 125.8l-1.8-.8v1.2M18.2 121v1.1l-1.1-1-.2-.1-.3 .1-.2 .3v.4l.2 .2M21.5 129.5v-1.1l.6 .6 .2-.5h.8l.1 .2v.5l-.1 .3M22.1 130.3h1.1M22.2 122.6l.4 .4v.3l-.4 .4h-.4l-.3-.2v-.5l.1-.3a1.18 1.18 0 0 1 1.6 .4v.4M22.6 130v1l-1.1-.3M23.1 127.7h.1M23.2 126.4h-1.7l.5 .6M23.2 125l-1.7-.8v1.1M23.2 121.7l-1.7-.8v1.2"/>
<path d="M23.2 125.9v1.1M29.1 138.8v-1.1l.7 .6 .1-.5 .6-.1 .3 .3v.6l-.2 .2M29.1 136.2v.7l.8 .1-.1-.2v-.5l.3-.2h.4a.59 .59 0 0 1 .1 .9M29.1 133.1v-1.1l.7 .5 .1-.5h.6l.3 .3v.5l-.2 .3M29.2 133.8a1.28 1.28 0 0 1 1.6 .2 .89 .89 0 0 1-.9 .6 .89 .89 0 0 1-.8-.6zM29.2 130.6a.96 .96 0 0 1 1.6 .3 1.16 1.16 0 0 1-1.7 0zM29.2 128.9a.96 .96 0 0 1 1.6 .3 .95 .95 0 0 1-.9 .5 .95 .95 0 0 1-.8-.6zM29.7 126.6h1.1M29.7 124.3h1.1M30.6 135.3h.2M30.8 125.9h-1l-.1 .5 .1 .2M30.8 125.2l-1 .1-.1 .4 .2 .2"/>
<path d="M30.8 123.6l-1 .1-.1 .4 .1 .2M30.8 122.9h-.9a.35 .35 0 0 0-.2 .3 .35 .35 0 0 0 .2 .4M38.6 128.8h1.1M38.6 126.5h1.1M38.7 134.2l.3 .1 .1 .5a.6 .6 0 0 1-1 0v-.3a1.06 1.06 0 0 1 1.6 .2v.3M38.7 132.5l.4 .3v.3l-.4 .4-.6-.2v-.5a1.06 1.06 0 0 1 1.6 .2v.3M38.7 131.2l.4-.3h.3l.3 .3v.5l-.6 .2-.4-.4-.1-.6h-.4l-.1 .3v.5l.4 .2 .2-.4M39.6 137.5h.1M39.7 138.7h-1.6l.4 .5M39.7 136.4l-1.6-.7v1.2M39.7 128.1h-1l-.1 .5 .2 .2M39.7 127.3l-1 .1-.1 .4 .3 .3"/>
<path d="M39.7 125.8l-1 .1-.1 .4 .2 .2M39.7 125l-1 .1-.1 .4 .3 .3M39.7 138.2v1M46 133.5h1.2M46 131.2h1.2M46.2 137.1l.3 .4-.1 .5-.2 .1h-.4l-.3-.1-.1-.5 .2-.3a1.18 1.18 0 0 1 1.6 .4v.4M46.2 135.8l.3-.3 .5 .1 .2 .2-.1 .6-.6 .1-.2-.1-.3-.8-.2-.1-.3 .2-.1 .5 .2 .2 .2 .1 .4-.3M47.2 139.5l-1.8-.8v1.1M47.2 132.7l-1.1 .1-.1 .4 .2 .3M47.2 132h-1.1l-.1 .5 .3 .2M47.2 130.4l-1.1 .1-.1 .4 .2 .3M47.2 129.7h-1.1l-.1 .5 .3 .2"/>
<path d="M56.4 137.8l59.3 .1M57.4 137.8v22.4M57.4 137.8l1.1 1.9M57.4 137.8l-1 1.9M61 139.6h1.2M62.2 138.8l-1.1 .1-.1 .4 .2 .3M62.2 138.1h-1.1l-.1 .5 .3 .2M66.8 139l.1 37.7M99 127.5h.9l.1-.3-.1-.4-.2-.2h-.7v1.8M99.4 127.5l.6 .9M101.1 126.5l-.4 1.3h1M101.6 127.2v1.2"/>
<path d="M112.2 125.3h.8l.1-.4-.2-.2-.7-.1v1.7h.6l.4-.4a.46 .46 0 0 0-.5-.6M113.7 124.6h1.2l-1.2 1.7h1.2M115.4 125.1l.5-.5v1.7M115.4 126.3h1.1M116.5 138.7l.2 37.8M129.8 135a.6 .6 0 0 1 .7-.3 .6 .6 0 0 1 .4 .6v.6a.59 .59 0 0 1-.6 .6 .59 .59 0 0 1-.6-.6zM130.1 136.1l.3 .1 .6 .5M131.6 134.9l.2-.2h.4l.3 .2v.4l-1 1.2h1M133.1 138.4a.71 .71 0 0 0-.1 .9 .71 .71 0 0 0 .9 .2 .67 .67 0 0 0 .7-.4 .67 .67 0 0 0-.1-.7M136.2 139.6l1.8 .6-1.8 .5M140.7 138.8l-.1 .7 .2 .2h.5l.3-.8 .3-.1 .4 .3-.1 .7M145 138.3l1.7 .6-1.7 .6"/>
<path d="M149.3 139.6l1.8 .6-1.8 .5M153.8 139a.9 .9 0 0 1 1.1-.3 .9 .9 0 0 1 .5 1h-1.7zM158.2 139a.9 .9 0 0 1 1.1-.3 .9 .9 0 0 1 .5 1h-1.7zM162.4 139.3h1.8l-1.8 .9h1.8M171.3 140a1.03 1.03 0 0 1 1.6 .2 .96 .96 0 0 1-1.7 0zM172.3 136.6l.6-.2a1.05 1.05 0 0 1 .4 1.5 .6 .6 0 0 1-.7 .2 .6 .6 0 0 1-.4-.6zM172.5 137.7l.3 .1 .6 .5M173.9 136.9l.6-.5v1.7M173.9 138.1h1.1M177.3 139.7v1M181.7 139.7v1.1l-1-1-.2-.1-.4 .1-.1 .3 .1 .6M189.3 139.9h1.2"/>
<path d="M189.9 139.7v1l-1.2-.5M193.1 139.8v.8l.8 .1-.1-.3v-.5l.3-.2 .6 .1 .2 .3-.2 .6M195.6 134.6l.9-.1 .1-.3v-.4l-.3-.2h-.7v1.7M196 134.6l.6 .7M197.3 134.2l.4-.6v1.7M197.3 135.3h.9M211.3 129.1h2M211.3 128.1h2M211.3 125.7h2M211.3 124.5h2M212 132.6v.4l.3 .1M212 134.9h1.3"/>
<path d="M212 133.1h1.3M212 129.7v.7M212 135.9l.3-.1h.6l.4 .4v.2l-.4 .4-.8-.1a.56 .56 0 0 1-.1-.8zM212.1 137.6l.8-.1 .4 .5v.2l-.4 .4h-.6l-.3-.4zM212.2 124.5v1.2M212.5 131.1l.1 .7a.36 .36 0 0 0 .5 .2l.2-.2v-.5l-.2-.2M212.5 121l.1 .7a.36 .36 0 0 0 .5 .2l.2-.2v-.4l-.2-.3M213.1 122.8l.2 .3v.3l-.2 .2h-1.1a.6 .6 0 0 1 .2-.9h.3l.1 1M213.3 139.4h-2l1.4 .7-1.4 .7h2M213.3 134.1h-1.1a.52 .52 0 0 0-.1 .8M213.3 131.1l-1.3 .1v.8M213.3 129.7l-.3 .5h-1.7"/>
<path d="M213.3 121h-1.1a.6 .6 0 0 0-.2 .9M214.1 138.6h1.5v.5l-.3 .2-.5-.1-.2-.2 .1-.4M214.6 139.7v.2l.3 .3M214.6 136.8l1 .3-.7 .3 .7 .3-1 .3M214.6 134.4v.2l.3 .2M214.6 134.8h1M215 135.6l.1 .6h.5v-.6l-.9 .1v.5M215.6 133.3v.6l-.2 .1-.7-.1v-.6l.3-.1 .1 .8M218.1 139.9l-1 .1-.1 .4 .2 .2M218.1 137.3v.9l-.9-.9-.6 .1-.1 .5 .2 .2M219.6 139.9v.3l.2 .2M219.6 138.8h.9v.6h-.9z"/>
<path d="M219.6 137.4v.6l.2 .1h.5l.2-.1v-.6M219.9 136.1l.3 .7 .4-.2-.1-.5M220.6 136.1l-1 .1v.5M220.6 135.2l-.3 .1h-1.2M223.6 139v-.6l-.1-.3-.4-.1-.3 .2-.1 .8h1.7M224.4 137l-1.7-.7v1.2M224.4 138l-.8 .6M235.7 138h1.4l.3 .4v.3l-.3 .4h-1.4M237.4 136.9h-1.7l.5 .4M237.4 136.4v.9M12.8 158.7l1 2M14.9 158.7l-1.1 2"/>
<path d="M18.3 158.7l1 2M20.4 158.7l-1.1 2M22.9 158.3l1 1.9M24.9 158.3l-1 1.9M30.8 159l1 1.9M32.8 159l-1 1.9M38 140.9l.1-1 .5 .5 .1-.3 .3-.2 .6 .1 .1 .2v.5l-.1 .2M39.9 158.4l.9 1.9M41.9 158.4l-1.1 1.9M45.4 143a.7 .7 0 0 0 .8 .9h.7l.2-.2 .1-.5-.2-.2-.6-.1-.2 .1-.1 .6 .3 .3M45.4 140.6a.7 .7 0 0 0 .8 .8h.7l.2-.1 .1-.5-.2-.3-.6-.1-.2 .2-.1 .5 .3 .3M47 142.2h.2"/>
<path d="M47.1 158.3l1 1.9M47.2 144.6v1l-1.3-1-.3 .1-.2 .2 .2 .6M49.1 158.3l-1 1.9M54.9 154.6v-1.1l.7 .6 .2-.5h.7l.2 .3v.5l-.2 .2M55 151.3a1.18 1.18 0 0 1 1.7 .2 .96 .96 0 0 1-1.6 .4l-.2-.2zM55.5 144.1h1.2M55.5 141.9h1.2M55.7 147.9l.3 .3-.1 .4-.2 .2h-.5l-.2-.2-.1-.4 .2-.2a1.44 1.44 0 0 1 1.6 .3v.3M56.4 158.3l1 1.9M56.5 152.9h.2M56.7 155.7h-1.8l.5 .5M56.7 149.5v1.1l-1-1-.3-.1-.3 .1-.2 .2v.4l.2 .3"/>
<path d="M56.7 146.9l-1.8-.8v1.2M56.7 143.4l-1.1 .1-.1 .4 .2 .2M56.7 142.7l-1.1 .1-.1 .3 .3 .3M56.7 141.1l-1.1 .1-.1 .4 .2 .3M56.7 140.3l-1.1 .1-.1 .4 .3 .3M56.7 155.2v1M58.5 158.3l-1.1 1.9M60.4 153.4h12.5M60.4 155.3l1-1.9 1 1.9M60.4 158.3l1 1.9M60.6 149a.96 .96 0 0 1 1.6 .4 1.11 1.11 0 0 1-1.8 0zM60.6 147.4a.96 .96 0 0 1 1.6 .4 1.11 1.11 0 0 1-1.8 0z"/>
<path d="M60.6 145.8a1 1 0 0 1 1.6 .3 1.05 1.05 0 0 1-1.8-.1zM60.6 144.1a.96 .96 0 0 1 1.6 .4 1.11 1.11 0 0 1-1.8 0zM61 141.9h1.2M61 151.4h1.2M61.4 153.7v6.5M61.6 151.3v1l-1.3-.5M62 150.6h.2M62.2 141.1l-1.1 .1-.1 .4 .2 .3M62.2 140.4h-.9a.35 .35 0 0 0-.3 .4 .35 .35 0 0 0 .3 .3M62.4 158.3l-1 1.9M72.5 145.5h.9M72.5 144.7v1.7"/>
<path d="M73.4 144.7v1.7M73.8 154.2v11.1M74.2 144.8l.3-.1h.4l.2 .1 .1 .4-.1 .2-1 1h1.1M132.9 140.2h1.8l-1.8 1h1.8M136.2 141.3v.8l.8 .1-.1-.3v-.6l.3-.1 .6 .1 .2 .2v.4l-.2 .3M140.6 140.4v.9h1.7v-.9M141.4 140.7v.6M141.5 143l-.1-.8-.2-.2-.4 .1-.2 .3v.6h1.7M142.3 142l-.8 .6M145 143.5v-1.1l.6 .6 .1-.4 .2-.2 .6 .1 .2 .3v.4l-.2 .3M145 141v-1l.6 .5v-.3l.3-.2 .6 .1 .2 .1v.6l-.2 .2M146.5 141.7h.2"/>
<path d="M149.3 141.3v.8l.9 .1-.2-.3 .1-.6 .2-.1 .6 .1 .2 .2v.4l-.2 .3M153.7 140.4h1.7l-1.7 1h1.7M153.8 142.3a.8 .8 0 0 0 .4 .9 .8 .8 0 0 0 .9-.2 .52 .52 0 0 0 .1-.8h-.5v.3M158.1 140.4h1.7l-1.7 1h1.7M158.2 142.3a.8 .8 0 0 0 .4 .9 .8 .8 0 0 0 1-.2 .52 .52 0 0 0 0-.8h-.6v.3M162.4 141.7l1.8 .6-1.8 .5M162.4 141.1h1.8M172.4 141.3v.9M172.9 141.2l-1.7 .6 1.7 .6M176.8 141.3v.9M177.3 141.2l-1.7 .6 1.7 .6M177.3 140.2h-1.7l.5 .5"/>
<path d="M181.2 141.3v.9M181.7 141.2l-1.7 .6 1.7 .6M184.4 140.8v-1.1l.6 .5 .3-.5 .6 .1 .2 .3v.4l-.2 .3M185.5 141.3v.9M186.1 141.2l-1.7 .6 1.7 .6M189.9 141.3v.9M190.5 141.2l-1.7 .6 1.7 .6M194.4 141.3v.9M194.9 141.2l-1.8 .6 1.8 .6M200 145.5h1M200 144.7v1.7M201 144.7v1.7"/>
<path d="M201.3 154.2v42.6M201.6 144.7h1.1l-.6 .6 .5 .2v.8l-.2 .1h-.5l-.3-.1M214.1 155v.7h1.5v-.7M214.1 151.9h1.5l-1.5 .9h1.5M214.1 149.4a1.03 1.03 0 0 1 1.5-.1v.6l-.2 .1a1.09 1.09 0 0 1-1.3-.3zM214.1 143.1h1.5M214.1 142.3h1.5M214.2 156.3v.1a.56 .56 0 0 0 .3 .9l.9-.1 .2-.2-.1-.7M214.6 148.4h1.5M214.6 145.7h1M214.6 140.2h1M214.7 148.4l-.1-.4 .3-.3 .7 .1v.6"/>
<path d="M214.8 142.3v.8M214.8 155.1v.6M214.9 154.3v-.6a.47 .47 0 0 0-.4-.3 .47 .47 0 0 0-.4 .3v.6h1.5M215 140.9l.1 .6h.5v-.6h-.9v.6M215.6 146.4v.6l-.2 .1-.7-.1v-.6l.3-.1 .1 .8M215.6 145.1l-.9 .1-.1 .3 .2 .2M215.6 153.5l-.7 .5M216.5 156h.2M216.5 146.8l1.6 .5-1.6 .5M216.5 142.7h.2M217 144.5v.2l.4 .2M217 141.5l.4-.2h.4l.3 .2v.3l-.1 .2h-.8z"/>
<path d="M217 156h1.1M217 152.6h1.1M217 144.9h1.1M217 142.7h1.1M217 140.6h1.1M217.1 154.6l-.1 .5 .4 .2 .6-.1 .1-.1v-.5M217.1 150.7a.33 .33 0 0 0 0 .5 .33 .33 0 0 0 .4 .1l.1-.6h.3l.2 .2v.4M217.1 143.5l-.1 .3 .3 .3 .2-.1 .1-.5h.5v.6M218.1 153.4v.4l-.2 .2h-.8v-.6l.4-.1 .1 .7M218.1 149.4v.5l-.2 .2-.8-.1v-.6h.4l.1 .7M218.1 145.7v.4l-.2 .2-.8-.1-.1-.4 .5-.2 .1 .7M218.1 156.5v.8h-1.6"/>
<path d="M218.1 152h-1l-.1 .4 .2 .2M219.1 156.4l.1 .9h.4l.3-.7 .3-.2 .4 .4-.1 .5M219.1 142.5h.1M219.6 154.5v.2l.2 .2M219.6 153.4l.2-.2h.5l.2 .2 .1 .3-.3 .3h-.5l-.2-.1zM219.6 148.4l1.3 .5 .2 .2M219.6 143.1v.6l.2 .2h.5l.2-.2v-.6M219.6 155.4v.6M219.6 154.9h1M219.6 152.5h1M219.6 142.5h1M219.6 140.4h1"/>
<path d="M219.8 146.7v-.8l-.2-.1h-.4l-.1 .9h1.5M220.5 150.5l.1 .4-.2 .3-.6 .1-.2-.2v-.6h1.2l.3 .3-.1 .4M220.5 144.6v.6h-.9v-.6l.3-.1 .2 .7M220.5 141.8l.1-.5-.2-.2-.6-.1-.2 .2v.6h1.5M220.6 155.4v.2l-.3 .1h-1.2M220.6 151.9l-1 .1 .1 .5M220.6 149.6l-.3 .2h-1.2M220.6 148.8l-1 .3M220.6 145.8l-.8 .5M227.5 144.7v1.7M227.5 145.5h1.1M228.6 144.7v1.7"/>
<path d="M228.9 154.2v51.6M229.7 153.4h38.6M230.1 144.7h-.4a1.32 1.32 0 0 0-.3 1.6l.2 .1 .5-.1 .1-.2v-.4l-.3-.4-.5 .1-.1 .3M243.4 156.8h1M243.9 156.8v1.7M245 157.6l.8-.1 .1-.6-.2-.1h-.7v1.7M246.6 156.9l.2-.1h.5l.2 .1 .1 .4-1.1 1.2h1.1M256.5 158.3l1 1.9M257.5 153.4v6.8M257.5 153.4l.9 1.9M257.5 153.4l-1 1.9M258.4 158.3l-.9 1.9"/>
<path d="M260.2 158.5h1.1M261.3 159.4h-1l-.1 .4 .3 .3M261.3 157.8l-1 .1-.1 .4 .2 .2M261.3 157l-1 .1-.1 .4 .3 .3M266.3 151.4l1 2M268.3 151.4l-1 2M12.8 160.7h60.1M39.9 160.3l79.9 .2M56.4 160.2l59.3 .1M66.7 170.6h33.3M66.7 170.6l1.9 1.1M66.9 164.3h6.9"/>
<path d="M66.9 164.3l2 1M66.9 175.7l2 1M68.6 169.6l-1.9 1M68.8 174.7l-1.9 1M68.9 163.3l-2 1M69 179.2l-1.9 1M71.8 163.3l2 1M73.8 164.3l-2 1M75.4 168.2l.5-.5v1.8M75.4 169.5h.9M76.6 163.3l-.4 1.2h1M76.9 163.9v1.2"/>
<path d="M77.8 164.9v.2M78 168.4l-.3 .4-.5-.1-.2-.3v-.4l.2-.2 .5-.1 .2 .1a1.18 1.18 0 0 1-.4 1.7h-.3M78.8 163.5l.2-.1a.93 .93 0 0 1 .6 .8 .93 .93 0 0 1-.6 .9l-.2-.2-.2-.5zM78.8 169.3v.2M79.4 167.7h1.1l-.6 .7 .5 .1v.8l-.3 .2h-.5l-.2-.2M80.4 163.5l.2-.1a.88 .88 0 0 1 .7 .8 .88 .88 0 0 1-.7 .9l-.2-.2-.2-.5zM82 163.5l.3-.1a.88 .88 0 0 1 .6 .8 .88 .88 0 0 1-.6 .9l-.4-.4zM82 167.7h-.8v.8l.2-.1h.5l.2 .3-.1 .6-.3 .2-.5-.2M82.9 167.8l.3-.1a.96 .96 0 0 1 .4 1.6l-.2 .2a.96 .96 0 0 1-.5-1.7zM83.7 163.5l.2-.1a.88 .88 0 0 1 .7 .8 .88 .88 0 0 1-.7 .9l-.2-.2-.2-.5zM83.9 172.8l.6-.1 .2 .1 .1 .4-1 1.3h1M84.5 167.8l.3-.1a.96 .96 0 0 1 .4 1.6l-.2 .2a.96 .96 0 0 1-.5-1.7z"/>
<path d="M85.8 173.4l-.3-.3 .1-.3 .2-.1 .5 .1 .2 .2-.1 .3-.8 .2-.1 .3v.3l.3 .4h.3l.4-.4-.1-.5-.3-.2M86.1 177.2h1l-.6 .7 .5 .2v.7l-.3 .1h-.4l-.2-.1M86.6 164l.2-.1 .4 .1v1.1M86.6 163.9v1.2M87.2 174.3v.1M87.2 164.1l.3-.2 .4 .1 .1 1.1M87.4 168.4l.3-.1 .4 .1 .1 1.1M87.4 168.3v1.2M87.8 177.8l.5-.6v1.7M87.8 178.9h1M88.2 168.5l.2-.2 .5 .1v1.1M88.9 164l.2-.1 .4 .1 .1 1.1"/>
<path d="M88.9 163.9v1.2M88.9 173.4l-.3 .4h-.3l-.4-.4v-.4l.2-.2 .5-.1 .3 .1a1.17 1.17 0 0 1-.5 1.6h-.3M89.4 178.8v.1M89.6 164.1a.35 .35 0 0 1 .4-.2 .35 .35 0 0 1 .3 .2v1M89.6 173.2l.4-.5v1.7M89.6 174.4h.9M89.7 168.4l.3-.1 .4 .1 .1 1.1M89.7 168.3v1.2M90.2 177.4l.3-.2h.4l.2 .2 .1 .4-.1 .2-1 .9h1.1M90.5 168.5l.2-.2 .4 .1 .1 1.1M91.5 172.8l.1-.1a.89 .89 0 0 1 .7 .8 .89 .89 0 0 1-.7 .9 1.06 1.06 0 0 1-.1-1.6zM91.7 177.2h1.2l-.7 1.7"/>
<path d="M92.8 172.7h1.1l-.6 .7h.5v.8l-.3 .2h-.5l-.2-.2M93.7 177.4l.2-.2a1.01 1.01 0 0 1 .2 1.7 .91 .91 0 0 1-.4-1.5zM95.1 177.4l.3-.2h.4l.3 .5v.2l-1.1 1h1.1M95.9 173.4l.2-.2 .5 .1v1.1M95.9 173.2v1.2M96.6 173.4l.3-.2 .4 .1 .1 1.1M98.1 169.6l1.9 1M98.2 177.9l.2-.1h.4l.1 1.1M98.2 173.4l.2-.2 .4 .1 .1 1.1M98.2 173.2v1.2M98.2 177.8v1.1M98.9 178l.3-.2h.3l.2 1.1"/>
<path d="M98.9 173.4l.3-.2 .4 .1 .1 1.1M99.3 160.1l-76.4 .1M100 170.6l-1.9 1.1M100.5 177.9l.2-.1h.4l.1 1.1M100.5 177.8v1.1M101.2 178l.3-.2h.4l.1 1.1M114.8 174.5l1.9 1M116.7 175.5l-49.8 .2M116.7 175.5l-1.9 1M119.1 179l1.9 1-1.9 1.1M122.7 179.1l-1.9 1 1.9 1M129.7 177.7l.5-.5v1.7"/>
<path d="M129.7 178.9h1M132.4 177.9l-.4 .4h-.3l-.3-.4v-.4l.1-.3h.5l.3 .1a1.18 1.18 0 0 1-.4 1.6h-.4M133.1 178.8v.1M134.7 177.2a.7 .7 0 0 0-.9 .7v.7l.2 .3h.5l.2-.1 .1-.6-.1-.3-.5-.1-.4 .4M135.4 177.7l.5-.5v1.7M135.4 178.9h1M137.4 177.2h.3l.3 .1v1v.5l-.3 .1a.96 .96 0 0 1-.4-1.6zM138.9 177.3l.2-.1a.96 .96 0 0 1 .5 1.6l-.3 .1a.96 .96 0 0 1-.4-1.6zM141.8 177.9l.2-.1h.4l.1 1.1M141.8 177.8v1.1M142.5 178l.3-.2h.4v1.1M144.1 177.9l.2-.1h.4l.1 1.1"/>
<path d="M144.1 177.8v1.1M144.8 178l.3-.2h.4l.1 1.1M152.6 179.1l2 1M174.5 160.3l-143.7 .6M205.5 170.2l.6 1.7 .6-1.7M207.3 171.2h1.3M210.4 170.4a.8 .8 0 0 0-1.1 .5 .8 .8 0 0 0 .8 1l.3-.2M211.1 170.2v1.4l.4 .3h.3l.3-.3v-1.4M212.7 170.2h1M213.1 170.2v1.7M229.7 160.2h28.7M259.7 168a.96 .96 0 0 1 1.6 .4 .95 .95 0 0 1-.9 .4 .95 .95 0 0 1-.8-.6z"/>
<path d="M259.7 166.4a.96 .96 0 0 1 1.6 .3 .95 .95 0 0 1-.9 .5 .95 .95 0 0 1-.8-.6zM259.7 164.7a1.28 1.28 0 0 1 1.6 .2 .89 .89 0 0 1-.8 .6 .89 .89 0 0 1-.9-.6zM259.7 163.1a.96 .96 0 0 1 1.6 .3 .95 .95 0 0 1-.9 .5 .95 .95 0 0 1-.8-.6zM260.2 170.4h1.1M260.2 160.8h1.1M260.8 170.1v1.1l-1.3-.4M261.2 169.5h.1M261.3 160.1h-1l-.1 .5 .2 .2M66.9 188.6l2 1M66.9 195.8h134.4M66.9 195.8l2 1M67.1 180.2l1.9 1"/>
<path d="M68.9 187.6l-2 1M68.9 194.8l-2 1M113.8 185.6a.72 .72 0 0 0-.7 .8v.6l.3 .3 .5-.1 .1-.6a.54 .54 0 0 0-.9 0M114.7 185.8l.2-.2h.5l.2 .2 .1 .3-.1 .3-1 .9h1.1M116.4 187.2v.1M117 185.6h1.2l-.7 1.7M119.7 185.6h-.9v.9l.2-.2h.4l.4 .3v.4l-.2 .2-.6 .1-.2-.1M120.6 185.8l.3-.2a.89 .89 0 0 1 .6 .9 .89 .89 0 0 1-.6 .8l-.3-.1-.2-.6zM121 181.1l-.2-74.5v74.5M122.2 185.8l.3-.2a.89 .89 0 0 1 .6 .9 .89 .89 0 0 1-.6 .8l-.3-.1-.2-.6zM125.1 186.4l.2-.2 .6 .2v.9M125.1 186.2v1.1"/>
<path d="M125.9 186.4l.2-.2 .5 .2v.9M126 192.9h1.2l-.8 1.7M127.4 186.3l.5-.1 .2 .2v.9M127.4 186.2v1.1M128.1 186.4l.3-.2 .5 .2v.9M128.1 193.6l-.3-.3a.47 .47 0 0 1 .5-.4 .47 .47 0 0 1 .4 .4l-.7 .4-.2 .2 .1 .5 .2 .2 .5-.1 .1-.2v-.4l-.3-.3M129.5 194.4v.2M130.4 193.1l.5-.2a1.16 1.16 0 0 1 0 1.7 .91 .91 0 0 1-.5-1.5zM132 193.1l.3-.2a.88 .88 0 0 1 .6 .9 .88 .88 0 0 1-.6 .8l-.3-.2-.1-.5zM133.7 193l.2-.1a.88 .88 0 0 1 .6 .9 .88 .88 0 0 1-.6 .8 1.35 1.35 0 0 1-.2-1.6zM135.3 193.1l.3-.2a.88 .88 0 0 1 .6 .9 .88 .88 0 0 1-.6 .8l-.3-.2-.1-.5zM138.2 193.6l.3-.2 .4 .1 .1 1.1"/>
<path d="M138.2 193.4v1.2M139 193.7l.1-.3 .5 .1 .1 1.1M140.5 193.6l.3-.2 .4 .1 .1 1.1M140.5 193.4v1.2M141.3 193.7a.35 .35 0 0 1 .3-.3 .35 .35 0 0 1 .3 .3v.9M154.6 180.1l-87.5 .1M154.6 180.1l-2 1M173.1 187.5l1.9 1M175 188.5l-108.1 .1M175 188.5l-1.9 1M199.3 194.8l2 1M201.3 195.8l-2 1"/>
<path d="M66.9 204.8h162M66.9 204.8l2 1M68.9 203.7l-2 1.1M140.9 202.6l-.3 .3h-.4l-.3-.3v-.5l.2-.2 .7 .1a1.18 1.18 0 0 1-.4 1.6h-.3M141.9 201.8l-.3 1.2h1M142.4 202.4v1.2M143.3 203.4v.2M144.2 202l.5-.1a1.18 1.18 0 0 1-.1 1.7h-.2a1.35 1.35 0 0 1-.2-1.6zM145.8 202l.6-.1a1.18 1.18 0 0 1-.1 1.7 .96 .96 0 0 1-.5-1.6zM147.4 202l.6-.1a1.18 1.18 0 0 1-.1 1.7 .96 .96 0 0 1-.5-1.6zM149.1 202l.5-.1a1.1 1.1 0 0 1-.2 1.7l-.3-.2-.1-.5zM152 202.6l.1-.1a.36 .36 0 0 1 .6 .1v1"/>
<path d="M152 202.4v1.2M152.7 202.6l.2-.2 .5 .1 .1 1.1M154.3 202.6l.3-.2 .4 .1v1.1M154.3 202.4v1.2M155 202.6l.2-.2 .5 .1v1.1M226.9 203.7l2 1.1M228.9 204.8l-2 1"/>
</g>
<g fill="#000">
<path d="M236.5 50.2l2.9 .3a1.8 1.8 0 0 1 1.4 1.8 1.8 1.8 0 0 1-1.6 1.7h-1.3v.9h.5v.6h-.8v.4l1.4-.1 .2 .3-.4 .5v1.1h.9v-1.1l-.3-.5 .5 .2v-.3h-.2l-.3 .1 .1-.3 .2-.1 1.4 .3v-.2l-.2 .1 .2-.4 .5 .5 .1 .9 .4-.6h.1l-.2 1 1.3 2.2v-2.9h-.6l-.4-.2v-.2l.4 .2 .3-.2-.2-.2-.5 .2 .1-.6h.3l.4 .3h1.5l-.1 3.5h2.2v-.1a2.27 2.27 0 0 0-1.1-1.6l-.2-.3v-.3h.2l.6 .8-.6-.8h-.3h.7l-.2-.5h-.2h.9l1 2.9 .1 .2 .9-2.5h-1.5v-.4l.1 .3h1.4l.2-.5-.5-.1v-.4h1.4l.2 .2h.2l.1-.2-.2-.1-.3 .1h-1.4v-.2h1.3l-.8-.7-.6 .3h-.7h-.2v.3a.72 .72 0 0 1-.2 1l-.1-.2-1.6-.1v-.4h1.5v.2h.3v-.3l-.3 .1h-1.5v-.2h1.4l.2-.3-.1-.1h-1.9l-.5-.4 .5 .2 .2-.1-.2-.3-.5 .2 .5-.4 .9 .2 2.3-.1a1.07 1.07 0 0 0 .6-1.4l-.5-.3 1.3-.1-1.3 .1-1.7-.2 3.1 .1-3.1-.1v2h-.7l-.1-.9-.5-.4h-.7a2.02 2.02 0 0 1-1.8 1.9l-.3 .1-.2-.1a1.98 1.98 0 0 1-1.2-1.4l.7 .1a.93 .93 0 0 0 .9 .7l.8-.3 .4-.5h-2.8v-1.7l.8-.1-.8 .1v-.2h.9l.2-.4-.2 .4h-.9l-.1-1.1-.5-.1v-.6h1.8v.5l-.5 .1-.1 .2v.7l.4-.3 .1 .2-.2 .7-.3 .2v1.2h2.2v-.6l1.2 .1 .8 .4-.8-.5h-1.2v-2.2l-.6-.2v-.5h1.7v.5l-.5 .1v2.2h.8l.6 .4v-.7l4-.1-4 .1v-.4l3 .1-3-.1v-.2h3.1h-3.1l-.1-1.3h.8v1.3l1.5-.1 .2-.2 .1-.4h.8l.3-.8-.4 .8a1.19 1.19 0 0 1-1.2-.5l-2.4-.1-.2-.1v-.5h2.4l1.1 .5 .5-.4h.6a2.06 2.06 0 0 1-.9 2.2l.9 .1 .1-.1h-.8l.9-.3 .1 .3a2.4 2.4 0 0 0-.8 1.8l-.2 .4 .7 .8a.5 .5 0 0 1 .5 .4 .5 .5 0 0 1-.3 .5v4.2l-2-.1-.2 .3-.3 .1-.4-.5v-.2l2.8 .2v-4h-.6l-1.2 3.8h-4.1v.6h-.5l-.5-.8h4.1l-.3-.6-2.4-.1-.1-2.9h-.2l-.1 .7v2.9h-1l-.9-1.4h-.5l.1 2.2h-1.8l.2-1.1h-1.6l.2 1.1h-1.8v-.6h.6v-.5h.6l.1 .5 .1-.6h1.9l.1 .6h1.2v-1.7l.5-.1-.8-1.3-.1 3.1h-.7l.1-.1v-.7h-2.4v.3h-.6v-.5h3v-1.2h-2.3v-.2l2.3 .1v-1.1h1.4l.2-.5-.2 .5h-1.4v-.4h-.6l-.1 1.1h-1l-.1-1.1-.3-.1-.1 1.5-.1-1.5-.1 2.9h-.6v-.2a1.15 1.15 0 0 0-.5-1.1l.1-.1 .3 .3-.3-.3h-.1l.1-.2 .3 .2 .1-.3-.1-1.2h-.8l-.3-.2v-.2l.3 .2h.2l.1-.2h1.6l.1 .2h.3v-.3h-.3l-.1 .1h-1.6l-.3-.2-.1 .2h-.2v-.2l.3-.2 .9 .2v-.4h-.8l-.4-.3 .2-.1 .4 .2v-.4h-.2l-.4 .2 .3-.4 .6 .2v-1.1l-.2-.4a.96 .96 0 0 1-.9-.5 .96 .96 0 0 1 0-1 1.23 1.23 0 0 1 .9 1.4l-.8-1.1 .3 .6 .6 .6v-.7h.8l.3-.5-.3 .5h-.8v-1.7h.8v.8l.4-.2 .1 .6-.2 1.1a1.39 1.39 0 0 0 1.8-1.6l-.7-.6h-2.7l-.3-.3v-.2l.5 .2 .1-.3-.3-.1-.1 .2h-.2zM83.4 131.3l.9-.1 2.1 .2a1.85 1.85 0 0 1 1.3 2.1 1.85 1.85 0 0 1-1.9 1.5h-.9v.8h.5v.7h-.8v.3l1.4-.1 .2 .5-.4 .5v.9h.9v-1.1l-.3-.3h.2l.1 .1 .3-.1v-.2l-.3-.1-.1 .3h-.2l.2-.5 1.6 .2v-.2l-.3 .1 .3-.3 .6 1.3v-.2l.4-.4v.6l-.2 .5 1.4 2.2v-2.9l-.9-.1-.2-.3h.3l.1 .1 .3-.1-.2-.2-.5 .2 .1-.6 1 .3h1.2l-.1 3.5h2.3l-.4-1a.44 .44 0 0 0-.5-.5l-.5-.7h.2l.6 .7-.1-.3-.4-.4h-.3v-.2l.6 .2-.3-.7h.9l1.1 3.1 .8-2.4h-1.4l-.1-.4h.1l.1 .3h1.3l.2-.6h-.5v-.4h1.4l.3 .2 .2-.3-1.9 .1v-.2h1.3l-.7-.8-.6 .3-1 .1 .2 .8-.3 .2v.3h-.1l-.1-.3h-1.5v-.4h1.4l.2 .2 .2-.3-1.8 .1v-.2l1.4-.1 .1-.2-2-.1-.4-.4 .6 .1v-.2l-.2-.1-.4 .2 .1-.3 3.4-.1a.87 .87 0 0 0 .8-.7 .87 .87 0 0 0-.6-1l1.3-.1h-3h3.1h-3.1v1.9h-.7v-.7l-.7-.6h-.6l-.1 .9a1.94 1.94 0 0 1-1.6 1.1l-.1 .1h-.3l-.1-.2-.7-.3-.5-.7v-.4h.5a1.11 1.11 0 0 0 1.1 .8 1.11 1.11 0 0 0 1.1-.8h-2.7l-.1-1.7h.8h-.8v-.1h.9l.2-.4-.2 .4h-.9v-1.1l-.6-.3v-.5h1.9l-.1 .6-.6 .2v.7l.5-.3 .1 .1a.81 .81 0 0 1-.6 1v1.3h2.2v-.5h.7a1.44 1.44 0 0 1 1.3 .5v-.2l-.5-.4-1.5 .1v-2.4l-.5-.1-.1-.6h1.7v.6l-.4 .1v2.1h.6l.7 .4v-.6h4h-4v-.5h3l-3-.1h3.1h-3.1l-.1-1.3h.8l.1 1.3h1a.61 .61 0 0 0 .7-.7h.8l.3-.9-.4 .9h-.7l-.1-.4-.7-.2-2.3-.1v-.6l2.8 .1 .8 .4 1-.4-.1 1.4-.7 .9 .9 .1h-.7l.8-.5 .2 .1-.7 1a2.09 2.09 0 0 1-.4 1.6l.7 .6 .3 .1 .2 .4-.3 1.2v3.4l-2-.1-.2 .4-.3 .1-.4-.6 2.8 .1v-4.1h-.2l-.4 .3-1.2 3.7h-1v-.2h-3v.7h-.5l-.6-.8h4.1l-.3-.7h-2.4v-2.9l-.2-.1-.1 3.7h-1.1l-.8-1.5h-.6v1.6l.2 .2-.1 .5-1.7 .1 .1-1.2h-1.6v.3l.2 .1v.7h-1.8v-.7h.6v-.4h.7v.4h.1l.1-.5h1.8l.2 .6h1.1l.1-1.8 .4-.2-.8-1.1v3.1h-.8l.1-.1v-.8h-2.3v.4h-.7v-.5h3v-1.3h-2.2v-.2l2.2 .1v-1h1.4l.3-.6-.3 .6h-1.4v-.4l-.5-.1-.1 1.3h-1.1v-1l-.1-.3-.2-.1-.1 1.5h-.1l-.1-1.4v2.9h-.7v-.7l-.4-.4 .1-.3 .2 .4-.3-.5h.4v-1.3l-.2-.2-.7 .1-.2-.1-.1-.3 .4 .2 .2-.2h1.7l.1 .2 .2-.1v-.2l-2 .1-.3-.2-.3 .2 .2-.4 1 .1v-.3h-.9l-.2-.3v-.1h.2l.1 .2 .3-.2-.1-.2-.5 .2 .2-.4 .6 .1v-1.3a1.28 1.28 0 0 1-1.1-1.7 1.4 1.4 0 0 1 1 1.5l-.9-1 .4 .7 .6 .4v-.8h.8l.3-.4-.4 .4h-.7v-1.6h.7v.8l.4-.2 .1 .1v.8l-.2 .8a1.29 1.29 0 0 0 1.6-.4 1.29 1.29 0 0 0-.1-1.7l-.7-.2h-2.4l-.3-.4 .4 .2 .2-.2-.1-.2-.5 .2z"/>
<circle cx="69.3" cy="55.1" r=".47"/>
<circle cx="70.5" cy="51.9" r=".47"/>
<circle cx="70.5" cy="58.3" r=".47"/>
<circle cx="73.7" cy="55.1" r="3.1"/>
<circle cx="73.7" cy="50.5" r=".47"/>
<circle cx="73.7" cy="59.6" r=".47"/>
<circle cx="77" cy="58.3" r=".47"/>
<circle cx="77" cy="51.9" r=".47"/>
<circle cx="78.2" cy="55.1" r=".47"/>
<circle cx="196.8" cy="55.1" r=".47"/>
<circle cx="198" cy="51.9" r=".47"/>
<circle cx="198" cy="58.3" r=".47"/>
<circle cx="201.3" cy="55.1" r="3.1"/>
<circle cx="201.3" cy="50.5" r=".47"/>
<circle cx="201.3" cy="59.6" r=".47"/>
<circle cx="204.5" cy="51.9" r=".47"/>
<circle cx="204.5" cy="58.3" r=".47"/>
<circle cx="205.7" cy="55.1" r=".47"/>
<circle cx="224.3" cy="55.1" r=".47"/>
<circle cx="225.6" cy="58.3" r=".47"/>
<circle cx="225.6" cy="51.9" r=".47"/>
<circle cx="228.9" cy="55.1" r="3.1"/>
<circle cx="228.9" cy="50.5" r=".47"/>
<circle cx="228.9" cy="59.6" r=".47"/>
<circle cx="232" cy="51.9" r=".47"/>
<circle cx="232" cy="58.3" r=".47"/>
<circle cx="233.3" cy="55.1" r=".47"/>
<circle cx="69.8" cy="78.9" r="1.4"/>
<circle cx="77.5" cy="78.9" r="1.57"/>
<circle cx="100.7" cy="74.1" r=".38"/>
<circle cx="117" cy="62.1" r=".89"/>
<circle cx="117.4" cy="79.4" r="2.16"/>
<circle cx="121.3" cy="62.1" r=".89"/>
<circle cx="122.8" cy="66.3" r=".38"/>
<circle cx="125.7" cy="62.1" r=".89"/>
<circle cx="127.4" cy="78.5" r="1.31"/>
<circle cx="130.1" cy="62.1" r=".89"/>
<circle cx="130.3" cy="66.1" r=".38"/>
<circle cx="131" cy="78.4" r=".72"/>
<circle cx="134.4" cy="62.1" r=".89"/>
<circle cx="135.3" cy="78.4" r=".72"/>
<circle cx="138.9" cy="62.1" r=".89"/>
<circle cx="139.7" cy="78.4" r=".72"/>
<circle cx="143.3" cy="62.1" r=".89"/>
<circle cx="144.1" cy="78.4" r=".72"/>
<circle cx="147.6" cy="62.1" r=".89"/>
<circle cx="149.2" cy="66.5" r=".38"/>
<circle cx="151.6" cy="79.8" r=".38"/>
<circle cx="152" cy="62.1" r=".89"/>
<circle cx="154" cy="70.2" r=".38"/>
<circle cx="156.4" cy="62.1" r=".89"/>
<circle cx="157.6" cy="79.4" r="2.16"/>
<circle cx="163.3" cy="69.8" r=".38"/>
<circle cx="163.3" cy="62.1" r=".89"/>
<circle cx="167.6" cy="69.8" r=".38"/>
<circle cx="167.7" cy="62.1" r=".89"/>
<circle cx="172" cy="69.8" r=".38"/>
<circle cx="172.1" cy="62.1" r=".89"/>
<circle cx="176.5" cy="62.1" r=".89"/>
<circle cx="180.8" cy="62.1" r=".89"/>
<circle cx="180.9" cy="77.9" r=".38"/>
<circle cx="185.2" cy="62.1" r=".89"/>
<circle cx="189.7" cy="62.1" r=".89"/>
<circle cx="194" cy="62.1" r=".89"/>
<circle cx="195.7" cy="74.8" r=".38"/>
<circle cx="196.1" cy="78.9" r=".38"/>
<circle cx="199.6" cy="74.6" r=".97"/>
<circle cx="199.6" cy="78.9" r=".97"/>
<circle cx="199.6" cy="70.2" r=".97"/>
<circle cx="217" cy="77.8" r=".38"/>
<circle cx="219.5" cy="71" r=".97"/>
<circle cx="223.8" cy="71" r=".97"/>
<circle cx="228.2" cy="71" r=".97"/>
<circle cx="232.6" cy="71" r=".97"/>
<circle cx="237" cy="74.8" r=".38"/>
<circle cx="237" cy="71" r=".97"/>
<circle cx="241.3" cy="71" r=".97"/>
<circle cx="95.1" cy="97.1" r=".38"/>
<circle cx="96.2" cy="80.1" r="1.06"/>
<circle cx="96.2" cy="91.3" r="1.06"/>
<circle cx="103.9" cy="80.1" r="1.06"/>
<circle cx="103.9" cy="91.3" r="1.06"/>
<circle cx="135.5" cy="84.7" r=".38"/>
<circle cx="139.7" cy="87.1" r=".38"/>
<circle cx="142" cy="91.6" r=".38"/>
<circle cx="144.1" cy="87.1" r=".38"/>
<circle cx="149.2" cy="89.9" r=".38"/>
<circle cx="163.5" cy="80.3" r=".38"/>
<circle cx="165.1" cy="93" r=".38"/>
<circle cx="169.4" cy="88.7" r=".38"/>
<circle cx="169.4" cy="96" r="1.06"/>
<circle cx="175" cy="83.1" r="1.31"/>
<circle cx="180.6" cy="96" r="1.06"/>
<circle cx="182.8" cy="86.4" r=".38"/>
<circle cx="183" cy="91.9" r=".38"/>
<circle cx="186.8" cy="97.9" r=".38"/>
<circle cx="186.8" cy="86.4" r=".38"/>
<circle cx="186.8" cy="91.6" r=".38"/>
<circle cx="188.9" cy="95.1" r=".38"/>
<circle cx="190.9" cy="83.1" r=".38"/>
<circle cx="190.9" cy="91.6" r=".38"/>
<circle cx="196.1" cy="83.7" r=".38"/>
<circle cx="199.2" cy="97.5" r=".38"/>
<circle cx="199.6" cy="83.3" r=".97"/>
<circle cx="199.6" cy="92" r=".97"/>
<circle cx="199.6" cy="87.7" r=".97"/>
<circle cx="219.2" cy="89.9" r=".38"/>
<circle cx="220.3" cy="84.5" r=".38"/>
<circle cx="223.8" cy="86.4" r=".89"/>
<circle cx="223.8" cy="90.7" r=".89"/>
<circle cx="225.7" cy="82.3" r=".38"/>
<circle cx="228.2" cy="86.4" r=".89"/>
<circle cx="228.2" cy="90.7" r=".89"/>
<circle cx="230.2" cy="98.5" r=".38"/>
<circle cx="230.7" cy="81.8" r=".38"/>
<circle cx="232.6" cy="86.4" r=".89"/>
<circle cx="232.6" cy="90.7" r=".89"/>
<circle cx="232.8" cy="83" r=".38"/>
<circle cx="236.7" cy="95.4" r=".38"/>
<circle cx="237" cy="86.4" r=".89"/>
<circle cx="237" cy="90.7" r=".89"/>
<circle cx="241.1" cy="96.5" r=".38"/>
<circle cx="241.3" cy="86.4" r=".89"/>
<circle cx="241.3" cy="90.7" r=".89"/>
<circle cx="244.4" cy="87.8" r=".38"/>
<circle cx="244.4" cy="93.2" r=".38"/>
<circle cx="96.2" cy="104.1" r=".38"/>
<circle cx="96.2" cy="119.7" r="1.06"/>
<circle cx="96.2" cy="108.5" r="1.06"/>
<circle cx="103.9" cy="119.7" r="1.06"/>
<circle cx="103.9" cy="108.5" r="1.06"/>
<circle cx="104.4" cy="102.7" r=".38"/>
<circle cx="108.6" cy="102.7" r=".38"/>
<circle cx="109.9" cy="119.9" r=".38"/>
<circle cx="154" cy="106.1" r=".38"/>
<circle cx="162.7" cy="100.2" r=".38"/>
<circle cx="164.4" cy="116.4" r=".38"/>
<circle cx="169.4" cy="103.8" r="1.06"/>
<circle cx="179.8" cy="112.2" r="3.1"/>
<circle cx="180.6" cy="103.8" r="1.06"/>
<circle cx="186.8" cy="102.7" r=".38"/>
<circle cx="193.2" cy="114.9" r=".38"/>
<circle cx="193.7" cy="119.2" r=".38"/>
<circle cx="194.4" cy="110.2" r=".38"/>
<circle cx="196.1" cy="100.6" r=".38"/>
<circle cx="196.8" cy="114.9" r=".89"/>
<circle cx="196.8" cy="106.1" r=".89"/>
<circle cx="196.8" cy="119.2" r=".89"/>
<circle cx="196.8" cy="110.5" r=".89"/>
<circle cx="201.3" cy="106.1" r=".89"/>
<circle cx="201.3" cy="114.9" r=".89"/>
<circle cx="201.3" cy="119.2" r=".89"/>
<circle cx="201.3" cy="110.5" r=".89"/>
<circle cx="201.6" cy="100.7" r=".38"/>
<circle cx="227.1" cy="100.8" r=".38"/>
<circle cx="234.7" cy="109.6" r=".38"/>
<circle cx="243.5" cy="109.5" r=".97"/>
<circle cx="243.5" cy="113.9" r=".97"/>
<circle cx="251.4" cy="113.9" r=".38"/>
<circle cx="95.4" cy="125" r=".38"/>
<circle cx="109.9" cy="134" r=".38"/>
<circle cx="109.9" cy="137.8" r=".89"/>
<circle cx="117.4" cy="120.4" r="2.16"/>
<circle cx="123" cy="129.9" r=".38"/>
<circle cx="123.1" cy="137.8" r=".89"/>
<circle cx="157.6" cy="120.4" r="2.16"/>
<circle cx="165.1" cy="138.7" r=".38"/>
<circle cx="165.1" cy="133.5" r=".38"/>
<circle cx="165.8" cy="129.9" r=".38"/>
<circle cx="166.8" cy="132.2" r=".38"/>
<circle cx="166.8" cy="139.5" r=".38"/>
<circle cx="196.1" cy="126.6" r=".38"/>
<circle cx="196.8" cy="123.6" r=".89"/>
<circle cx="198.7" cy="128.8" r=".38"/>
<circle cx="199" cy="122" r=".38"/>
<circle cx="201.3" cy="123.6" r=".89"/>
<circle cx="223.7" cy="124.8" r=".38"/>
<circle cx="228.2" cy="134.4" r=".38"/>
<circle cx="228.7" cy="131.7" r=".38"/>
<circle cx="237.6" cy="139.6" r=".38"/>
<circle cx="69.3" cy="153.3" r=".47"/>
<circle cx="70.5" cy="150.1" r=".47"/>
<circle cx="70.5" cy="156.5" r=".47"/>
<circle cx="73.7" cy="153.3" r="3.1"/>
<circle cx="73.7" cy="148.8" r=".47"/>
<circle cx="73.7" cy="157.8" r=".47"/>
<circle cx="77" cy="150.1" r=".47"/>
<circle cx="77" cy="156.5" r=".47"/>
<circle cx="78.2" cy="153.3" r=".47"/>
<circle cx="109.9" cy="145.5" r=".38"/>
<circle cx="132.8" cy="145.3" r=".89"/>
<circle cx="137.1" cy="145.3" r=".89"/>
<circle cx="141.5" cy="145.3" r=".89"/>
<circle cx="145.9" cy="145.3" r=".89"/>
<circle cx="147.8" cy="149" r=".38"/>
<circle cx="150.2" cy="145.3" r=".89"/>
<circle cx="152.1" cy="149" r=".38"/>
<circle cx="154.6" cy="145.3" r=".89"/>
<circle cx="159" cy="145.3" r=".89"/>
<circle cx="163.3" cy="145.3" r=".89"/>
<circle cx="169.4" cy="142.6" r=".38"/>
<circle cx="172.1" cy="145.3" r=".89"/>
<circle cx="174.2" cy="143.8" r=".38"/>
<circle cx="175.4" cy="140.9" r=".97"/>
<circle cx="176.5" cy="145.3" r=".89"/>
<circle cx="179.8" cy="140.9" r=".97"/>
<circle cx="180.8" cy="145.3" r=".89"/>
<circle cx="184.2" cy="140.9" r=".97"/>
<circle cx="185.2" cy="145.3" r=".89"/>
<circle cx="187.7" cy="143.3" r=".38"/>
<circle cx="189.7" cy="145.3" r=".89"/>
<circle cx="192" cy="146.9" r=".38"/>
<circle cx="194" cy="145.3" r=".89"/>
<circle cx="196.8" cy="153.3" r=".47"/>
<circle cx="198" cy="156.5" r=".47"/>
<circle cx="198" cy="150.1" r=".47"/>
<circle cx="201.3" cy="153.3" r="3.1"/>
<circle cx="201.3" cy="148.8" r=".47"/>
<circle cx="201.3" cy="157.8" r=".47"/>
<circle cx="202.1" cy="140.4" r=".38"/>
<circle cx="204.5" cy="156.5" r=".47"/>
<circle cx="204.5" cy="150.1" r=".47"/>
<circle cx="205.7" cy="153.3" r=".47"/>
<circle cx="224.3" cy="153.3" r=".47"/>
<circle cx="225.6" cy="150.1" r=".47"/>
<circle cx="225.6" cy="156.5" r=".47"/>
<circle cx="227.8" cy="141.5" r=".38"/>
<circle cx="228.9" cy="153.3" r="3.1"/>
<circle cx="228.9" cy="157.8" r=".47"/>
<circle cx="228.9" cy="148.8" r=".47"/>
<circle cx="232" cy="156.5" r=".47"/>
<circle cx="232" cy="150.1" r=".47"/>
<circle cx="233.3" cy="153.3" r=".47"/>
<circle cx="234.2" cy="143.8" r=".38"/>
<circle cx="244.3" cy="153.3" r="1.31"/>
</g>
<path d="M209.5 48.4v111.6" fill="none" stroke="#000" stroke-width=".42"/>
</svg>
